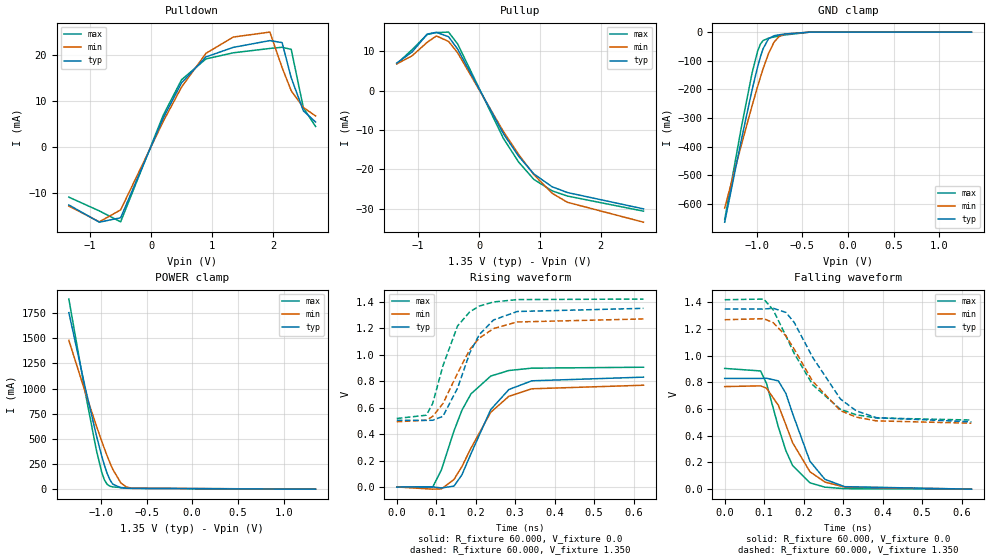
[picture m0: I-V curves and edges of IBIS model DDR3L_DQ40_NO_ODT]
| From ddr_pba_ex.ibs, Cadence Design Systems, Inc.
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|   Model DDR3L_DQ40_NO_ODT
[Model]   DDR3L_DQ40_NO_ODT
Model_type I/O
Polarity   Non-Inverting
Enable   Active-High
Vinl   =   0.624V
Vinh   =   0.727V
C_comp   1.682pF   1.658pF   1.699pF
C_comp_pullup   0.507pF   0.523pF   0.489pF
C_comp_pulldown 1.174pF   1.135pF   1.209pF
[Model Spec]
Vinh   0.727V   NA   NA
Vinl   0.624V   NA   NA
Vmeas   0.675V   NA   NA
[Temperature Range]   27.000   0.125k   -40.000
[Voltage Range]   1.350V   1.270V   1.420V
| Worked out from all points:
|   slope of the pulldown table from 0 to 0.203 V, typ, clamps not added: 31.7 ohm
|   slope of the pullup table from 0 to 0.203 V, typ, clamps not added: 35 ohm
|   GND clamp passes 1 mA (typ) near -0.50 V on its own axis
|   POWER clamp passes 1 mA (typ) near -0.46 V on its own axis
|   rising waveform, R_fixture 60.000, V_fixture 0.0: 20-80 % time 80.6ps typ, 88.1ps min, 74.4ps max; typ from 0 V to 0.83 V
|   rising waveform, R_fixture 60.000, V_fixture 1.350: 20-80 % time 71.4ps typ, 85.1ps min, 61ps max; typ from 0.504 V to 1.35 V
|   falling waveform, R_fixture 60.000, V_fixture 0.0: 20-80 % time 63.1ps typ, 70.8ps min, 58.8ps max; typ from 0.83 V to 0 V
|   falling waveform, R_fixture 60.000, V_fixture 1.350: 20-80 % time 105ps typ, 103ps min, 106ps max; typ from 1.35 V to 0.505 V
[Pulldown]
|Voltage   I(typ)   I(min)   I(max)
-1.35V    -12.71mA   -12.95mA   -11mA
-850mV    -16.48mA   -16.4mA    -14.01mA
-500mV    -15.51mA   -13.79mA   -16.4mA
200mV     6.324mA    5.595mA    6.939mA
500mV     14.01mA    13.08mA    14.69mA
900mV     19.68mA    20.46mA    19.24mA
1.35V     21.77mA    24.03mA    20.58mA
1.95V     23.25mA    25.11mA    21.53mA
2.15V     22.81mA    17.35mA    21.79mA
2.3V      15.11mA    12.27mA    21.33mA
2.5V      7.867mA    8.611mA    8.524mA
2.7V      5.436mA    6.755mA    4.464mA
[Pullup]
|Voltage   I(typ)   I(min)   I(max)
-1.35V    6.994mA    6.778mA    6.785mA
-1.1V     9.771mA    8.81mA     10.37mA
-850mV    14.35mA    12.26mA    14.25mA
-700mV    14.79mA    13.87mA    14.72mA
-500mV    13.68mA    12.48mA    14.85mA
-350mV    10.51mA    9.572mA    11.81mA
400mV     -10.97mA   -10.4mA    -12.15mA
650mV     -16.69mA   -16.24mA   -18.16mA
900mV     -21.19mA   -21.37mA   -22.58mA
1.2V      -24.45mA   -26.1mA    -25.49mA
1.45V     -25.91mA   -28.39mA   -26.8mA
2.7V      -30.07mA   -33.45mA   -30.65mA
[GND_clamp]
|Voltage   I(typ)   I(min)   I(max)
-1.35V    -663.5mA   -614.2mA   -654.4mA
-1.17V    -379.6mA   -396.8mA   -336.4mA
-1.05V    -201.2mA   -256.6mA   -142.3mA
-990mV    -121.8mA   -190.1mA   -66.76mA
-960mV    -87.12mA   -158.5mA   -42.47mA
-930mV    -58.01mA   -128.3mA   -29.57mA
-870mV    -23.03mA   -74.64mA   -21.11mA
-810mV    -12.75mA   -34.94mA   -17.06mA
-750mV    -9.218mA   -14.09mA   -13.42mA
-690mV    -6.687mA   -6.669mA   -9.983mA
-420mV    -175.8uA   -266.9uA   -234.9uA
1.35V     1.792nA    307.1nA    263.8pA
[POWER_clamp]
|Voltage   I(typ)   I(min)   I(max)
-1.35V    1.755A     1.479A     1.89A
-1.17V    1.006A     962.6mA    958.1mA
-1.05V    538.4mA    632.4mA    392.2mA
-990mV    328mA      475.7mA    167mA
-960mV    234.7mA    400.6mA    90.32mA
-930mV    154.2mA    328.7mA    47.17mA
-900mV    91.53mA    260.8mA    29.3mA
-870mV    50.28mA    198.1mA    22.68mA
-780mV    13.3mA     60.49mA    15.94mA
-720mV    9.309mA    21.57mA    12.7mA
-660mV    6.902mA    8.818mA    9.643mA
1.35V     -4.773nA   -193.5nA   -1.001nA
[Ramp]
| variable   typ   min   max
dV/dt_r 0.459/79.597p   0.426/88.799p   0.502/71.616p
dV/dt_f 0.465/0.105n   0.429/0.103n   0.493/0.107n
R_load = 50.000
| The next line is not an IBIS keyword
| [Initial Delay]   0.200ns   0.400ns   0.150ns
[Rising Waveform]
R_fixture= 60.000
V_fixture= 0.0
V_fixture_min= 0.0
V_fixture_max= 0.0
|time   V(typ)   V(min)   V(max)
0s        7.459uV    836.3uV    -14.97uV
91ps      1.618mV    -15.97mV   -121.5uV
113ps     -6.893mV   -14.1mV    129.5mV
145ps     7.183mV    57.71mV    425mV
165ps     92.45mV    155mV      580.1mV
188ps     252mV      293.8mV    704mV
238ps     585.1mV    564.7mV    838.4mV
284ps     736.7mV    685.5mV    880.3mV
342ps     802.5mV    742.2mV    898.1mV
625ps     830.2mV    769.2mV    905.2mV
[Rising Waveform]
R_fixture= 60.000
V_fixture= 1.350
V_fixture_min= 1.270
V_fixture_max= 1.420
|time   V(typ)   V(min)   V(max)
0s        504.2mV    493.4mV    517.9mV
75ps      503.7mV    504.9mV    542.8mV
91ps      504.5mV    533.9mV    631.9mV
117ps     534.6mV    630.8mV    916.3mV
154ps     747.7mV    860.4mV    1.217V
185ps     1.014V     1.039V     1.324V
209ps     1.151V     1.125V     1.367V
245ps     1.262V     1.197V     1.398V
305ps     1.326V     1.247V     1.416V
625ps     1.35V      1.27V      1.42V
[Falling Waveform]
R_fixture= 60.000
V_fixture= 0.0
V_fixture_min= 0.0
V_fixture_max= 0.0
|time   V(typ)   V(min)   V(max)
0s        830.3mV    769mV      905.2mV
91ps      829.9mV    774.5mV    886.1mV
106ps     831.8mV    756.4mV    791.6mV
136ps     811.5mV    628.4mV    465.1mV
155ps     717.2mV    482.5mV    288.6mV
172ps     567mV      348.4mV    177.6mV
216ps     208.9mV    130.3mV    47.46mV
254ps     73.56mV    53.34mV    14.97mV
304ps     18.67mV    16.11mV    3.685mV
625ps     34.77uV    69.72uV    38.66uV
[Falling Waveform]
R_fixture= 60.000
V_fixture= 1.350
V_fixture_min= 1.270
V_fixture_max= 1.420
|time   V(typ)   V(min)   V(max)
0s        1.35V      1.27V      1.42V
99ps      1.35V      1.278V     1.425V
123ps     1.356V     1.248V     1.343V
155ps     1.325V     1.149V     1.149V
176ps     1.25V      1.05V      1.018V
223ps     987.3mV    807.7mV    782mV
293ps     676.2mV    589.1mV    599.1mV
333ps     587.4mV    540.3mV    557.8mV
384ps     536mV      512.1mV    533.7mV
625ps     504.6mV    494.2mV    518.2mV
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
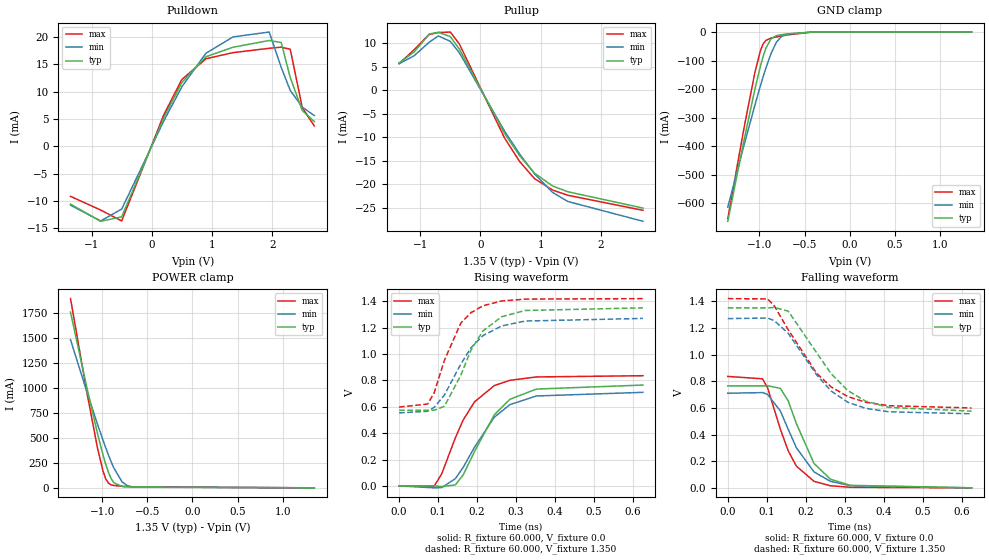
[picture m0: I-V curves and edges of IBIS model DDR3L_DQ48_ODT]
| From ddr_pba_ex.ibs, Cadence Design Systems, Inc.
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|   Model DDR3L_DQ48_ODT
[Model]   DDR3L_DQ48_ODT
Model_type I/O
Polarity   Non-Inverting
Enable   Active-High
Vinl   =   0.624V
Vinh   =   0.727V
C_comp   1.704pF   1.694pF   1.708pF
C_comp_pullup   0.520pF   0.541pF   0.498pF
C_comp_pulldown 1.183pF   1.153pF   1.209pF
[Model Spec]
Vinh   0.727V   NA   NA
Vinl   0.624V   NA   NA
Vmeas   0.675V   NA   NA
[Add Submodel]
|  Submodel_name   Mode
DDR3L_DQ_ODT60   Non-Driving
[Temperature Range]   27.000   0.125k   -40.000
[Voltage Range]   1.350V   1.270V   1.420V
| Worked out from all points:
|   slope of the pulldown table from 0 to 0.203 V, typ, clamps not added: 38 ohm
|   slope of the pullup table from 0 to 0.203 V, typ, clamps not added: 41.9 ohm
|   GND clamp passes 1 mA (typ) near -0.50 V on its own axis
|   POWER clamp passes 1 mA (typ) near -0.46 V on its own axis
|   rising waveform, R_fixture 60.000, V_fixture 0.0: 20-80 % time 89ps typ, 95.7ps min, 83.1ps max; typ from 0 V to 0.765 V
|   rising waveform, R_fixture 60.000, V_fixture 1.350: 20-80 % time 77.7ps typ, 92.1ps min, 67.3ps max; typ from 0.575 V to 1.35 V
|   falling waveform, R_fixture 60.000, V_fixture 0.0: 20-80 % time 68.4ps typ, 76.7ps min, 63.7ps max; typ from 0.765 V to 0 V
|   falling waveform, R_fixture 60.000, V_fixture 1.350: 20-80 % time 117ps typ, 113ps min, 120ps max; typ from 1.35 V to 0.576 V
[Pulldown]
|Voltage   I(typ)   I(min)   I(max)
-1.35V    -10.59mA   -10.79mA   -9.165mA
-850mV    -13.73mA   -13.67mA   -11.67mA
-500mV    -12.92mA   -11.5mA    -13.67mA
200mV     5.271mA    4.664mA    5.784mA
500mV     11.68mA    10.91mA    12.24mA
900mV     16.41mA    17.05mA    16.04mA
1.35V     18.15mA    20.04mA    17.16mA
1.95V     19.38mA    20.93mA    17.95mA
2.15V     19.02mA    14.47mA    18.16mA
2.3V      12.6mA     10.24mA    17.78mA
2.5V      6.561mA    7.181mA    7.107mA
2.7V      4.533mA    5.632mA    3.721mA
[Pullup]
|Voltage   I(typ)   I(min)   I(max)
-1.35V    5.83mA     5.65mA     5.655mA
-1.1V     8.144mA    7.344mA    8.639mA
-850mV    11.96mA    10.22mA    11.87mA
-700mV    12.33mA    11.56mA    12.27mA
-500mV    11.4mA     10.4mA     12.38mA
-350mV    8.759mA    7.978mA    9.845mA
400mV     -9.144mA   -8.667mA   -10.13mA
650mV     -13.91mA   -13.54mA   -15.14mA
900mV     -17.66mA   -17.81mA   -18.82mA
1.2V      -20.38mA   -21.75mA   -21.24mA
1.45V     -21.59mA   -23.66mA   -22.34mA
2.7V      -25.07mA   -27.88mA   -25.55mA
[GND_clamp]
|Voltage   I(typ)   I(min)   I(max)
-1.35V    -663.5mA   -614.2mA   -654.4mA
-1.17V    -379.6mA   -396.8mA   -336.4mA
-1.05V    -201.2mA   -256.6mA   -142.3mA
-990mV    -121.8mA   -190.1mA   -66.76mA
-960mV    -87.12mA   -158.5mA   -42.47mA
-930mV    -58.01mA   -128.3mA   -29.57mA
-870mV    -23.03mA   -74.64mA   -21.11mA
-810mV    -12.75mA   -34.94mA   -17.06mA
-750mV    -9.218mA   -14.09mA   -13.42mA
-690mV    -6.687mA   -6.669mA   -9.983mA
-420mV    -175.8uA   -266.9uA   -234.9uA
1.35V     1.792nA    307.1nA    263.8pA
[POWER_clamp]
|Voltage   I(typ)   I(min)   I(max)
-1.35V    1.755A     1.479A     1.89A
-1.17V    1.006A     962.6mA    958.1mA
-1.05V    538.4mA    632.4mA    392.2mA
-990mV    328mA      475.7mA    167mA
-960mV    234.7mA    400.6mA    90.32mA
-930mV    154.2mA    328.7mA    47.17mA
-900mV    91.53mA    260.8mA    29.3mA
-870mV    50.28mA    198.1mA    22.68mA
-780mV    13.3mA     60.49mA    15.94mA
-720mV    9.309mA    21.57mA    12.7mA
-660mV    6.902mA    8.818mA    9.643mA
1.35V     -4.773nA   -193.5nA   -1.001nA
[Ramp]
| variable   typ   min   max
dV/dt_r 0.419/87.454p   0.390/93.373p   0.458/80.404p
dV/dt_f 0.420/0.116n   0.391/0.112n   0.440/0.119n
R_load = 50.000
| The next line is not an IBIS keyword
| [Initial Delay]   0.200ns   0.400ns   0.150ns
[Rising Waveform]
R_fixture= 60.000
V_fixture= 0.0
V_fixture_min= 0.0
V_fixture_max= 0.0
|time   V(typ)   V(min)   V(max)
0s        8.065uV    771.2uV    -12.06uV
90ps      1.491mV    -13.68mV   917.6uV
109ps     -4.526mV   -11.95mV   91.01mV
144ps     8.599mV    55.57mV    364.3mV
164ps     83.69mV    140.7mV    499.3mV
193ps     259.9mV    293.2mV    636.9mV
244ps     540.3mV    521.5mV    761.1mV
284ps     657.3mV    616.9mV    800.9mV
352ps     734.7mV    682.3mV    826.5mV
625ps     765mV      709.9mV    835.9mV
[Rising Waveform]
R_fixture= 60.000
V_fixture= 1.350
V_fixture_min= 1.270
V_fixture_max= 1.420
|time   V(typ)   V(min)   V(max)
0s        574.5mV    554.4mV    598.4mV
73ps      573.7mV    565.8mV    621.2mV
90ps      574.2mV    596.4mV    707mV
116ps     604.3mV    689.3mV    952.6mV
158ps     838.3mV    923.3mV    1.234V
184ps     1.029V     1.047V     1.313V
215ps     1.176V     1.14V      1.366V
263ps     1.283V     1.213V     1.402V
323ps     1.33V      1.25V      1.416V
625ps     1.35V      1.27V      1.42V
[Falling Waveform]
R_fixture= 60.000
V_fixture= 0.0
V_fixture_min= 0.0
V_fixture_max= 0.0
|time   V(typ)   V(min)   V(max)
0s        765.2mV    710mV      836mV
89ps      764.9mV    714.6mV    818.3mV
102ps     766.2mV    701.3mV    751.4mV
135ps     746.2mV    576.1mV    438.4mV
155ps     652.3mV    438.9mV    277.7mV
176ps     481.6mV    300.5mV    162.7mV
221ps     183.4mV    119.9mV    49.01mV
263ps     65.3mV     49.31mV    15.75mV
314ps     18.8mV     16.37mV    4.308mV
625ps     42.97uV    88.37uV    39.85uV
[Falling Waveform]
R_fixture= 60.000
V_fixture= 1.350
V_fixture_min= 1.270
V_fixture_max= 1.420
|time   V(typ)   V(min)   V(max)
0s        1.35V      1.27V      1.42V
102ps     1.35V      1.274V     1.418V
119ps     1.354V     1.255V     1.367V
155ps     1.326V     1.159V     1.186V
228ps     1.013V     847.6mV    859mV
265ps     856.5mV    726.3mV    757.3mV
308ps     729.2mV    641.9mV    684.6mV
353ps     650.9mV    597mV      642.5mV
413ps     603.6mV    570.6mV    616.1mV
625ps     575.5mV    555.6mV    599.2mV
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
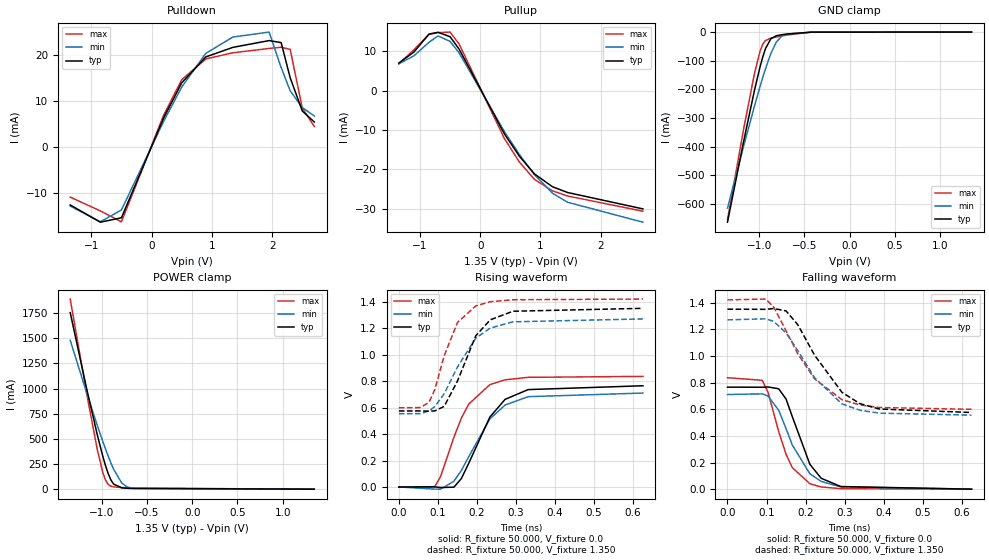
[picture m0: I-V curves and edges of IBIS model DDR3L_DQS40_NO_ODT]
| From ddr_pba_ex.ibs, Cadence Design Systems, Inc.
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|   Model DDR3L_DQS40_NO_ODT
[Model]   DDR3L_DQS40_NO_ODT
Model_type I/O
Polarity   Non-Inverting
Enable   Active-High
Vinl   =   0.624V
Vinh   =   0.727V
C_comp   1.684pF   1.658pF   1.703pF
C_comp_pullup   0.506pF   0.522pF   0.489pF
C_comp_pulldown 1.177pF   1.136pF   1.213pF
[Model Spec]
Vinh   0.727V   NA   NA
Vinl   0.624V   NA   NA
Vmeas   0.675V   NA   NA
[Temperature Range]   27.000   0.125k   -40.000
[Voltage Range]   1.350V   1.270V   1.420V
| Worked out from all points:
|   slope of the pulldown table from 0 to 0.203 V, typ, clamps not added: 31.7 ohm
|   slope of the pullup table from 0 to 0.203 V, typ, clamps not added: 35 ohm
|   GND clamp passes 1 mA (typ) near -0.50 V on its own axis
|   POWER clamp passes 1 mA (typ) near -0.46 V on its own axis
|   rising waveform, R_fixture 50.000, V_fixture 0.0: 20-80 % time 78.8ps typ, 86.4ps min, 71.6ps max; typ from 0 V to 0.765 V
|   rising waveform, R_fixture 50.000, V_fixture 1.350: 20-80 % time 68.6ps typ, 82.9ps min, 58.3ps max; typ from 0.575 V to 1.35 V
|   falling waveform, R_fixture 50.000, V_fixture 0.0: 20-80 % time 59.7ps typ, 67.6ps min, 55.4ps max; typ from 0.765 V to 0 V
|   falling waveform, R_fixture 50.000, V_fixture 1.350: 20-80 % time 104ps typ, 102ps min, 106ps max; typ from 1.35 V to 0.575 V
[Pulldown]
|Voltage   I(typ)   I(min)   I(max)
-1.35V    -12.71mA   -12.95mA   -11mA
-850mV    -16.48mA   -16.4mA    -14.01mA
-500mV    -15.51mA   -13.79mA   -16.4mA
200mV     6.324mA    5.595mA    6.939mA
500mV     14.01mA    13.08mA    14.69mA
900mV     19.68mA    20.46mA    19.24mA
1.35V     21.77mA    24.03mA    20.58mA
1.95V     23.25mA    25.11mA    21.53mA
2.15V     22.81mA    17.35mA    21.79mA
2.3V      15.11mA    12.27mA    21.33mA
2.5V      7.867mA    8.611mA    8.524mA
2.7V      5.436mA    6.755mA    4.464mA
[Pullup]
|Voltage   I(typ)   I(min)   I(max)
-1.35V    6.994mA    6.778mA    6.785mA
-1.1V     9.771mA    8.81mA     10.37mA
-850mV    14.35mA    12.26mA    14.25mA
-700mV    14.79mA    13.87mA    14.72mA
-500mV    13.68mA    12.48mA    14.85mA
-350mV    10.51mA    9.572mA    11.81mA
400mV     -10.97mA   -10.4mA    -12.15mA
650mV     -16.69mA   -16.24mA   -18.16mA
900mV     -21.19mA   -21.37mA   -22.58mA
1.2V      -24.45mA   -26.1mA    -25.49mA
1.45V     -25.91mA   -28.39mA   -26.8mA
2.7V      -30.07mA   -33.45mA   -30.65mA
[GND_clamp]
|Voltage   I(typ)   I(min)   I(max)
-1.35V    -663.5mA   -614.2mA   -654.4mA
-1.17V    -379.6mA   -396.8mA   -336.4mA
-1.05V    -201.2mA   -256.6mA   -142.3mA
-990mV    -121.8mA   -190.1mA   -66.76mA
-960mV    -87.12mA   -158.5mA   -42.47mA
-930mV    -58.01mA   -128.3mA   -29.57mA
-870mV    -23.03mA   -74.64mA   -21.11mA
-810mV    -12.75mA   -34.94mA   -17.06mA
-750mV    -9.219mA   -14.09mA   -13.42mA
-690mV    -6.687mA   -6.669mA   -9.983mA
-420mV    -175.8uA   -266.9uA   -234.9uA
1.35V     1.781nA    307.1nA    267.4pA
[POWER_clamp]
|Voltage   I(typ)   I(min)   I(max)
-1.35V    1.755A     1.479A     1.89A
-1.17V    1.006A     962.6mA    958.1mA
-1.05V    538.4mA    632.4mA    392.2mA
-990mV    328mA      475.7mA    167mA
-960mV    234.7mA    400.6mA    90.32mA
-930mV    154.2mA    328.7mA    47.17mA
-900mV    91.53mA    260.8mA    29.3mA
-870mV    50.28mA    198.1mA    22.68mA
-780mV    13.3mA     60.49mA    15.94mA
-720mV    9.309mA    21.57mA    12.7mA
-660mV    6.902mA    8.818mA    9.643mA
1.35V     -4.773nA   -193.5nA   -1nA
[Ramp]
| variable   typ   min   max
dV/dt_r 0.459/79.862p   0.426/87.109p   0.502/73.280p
dV/dt_f 0.465/0.106n   0.429/0.104n   0.493/0.108n
R_load = 50.000
| The next line is not an IBIS keyword
| [Initial Delay]   0.200ns   0.400ns   0.150ns
[Rising Waveform]
R_fixture= 50.000
V_fixture= 0.0
V_fixture_min= 0.0
V_fixture_max= 0.0
|time   V(typ)   V(min)   V(max)
0s        6.488uV    823.9uV    -14.21uV
92ps      1.282mV    -15.85mV   3.07mV
107ps     -3.761mV   -16.06mV   80.39mV
141ps     -883.8uV   43.86mV    376mV
160ps     63.79mV    125.2mV    520.2mV
179ps     180mV      229.5mV    626.7mV
233ps     528.4mV    514.1mV    773.3mV
272ps     662.3mV    619.2mV    809.9mV
331ps     736.1mV    682.6mV    828.7mV
625ps     765.1mV    710mV      835.9mV
[Rising Waveform]
R_fixture= 50.000
V_fixture= 1.350
V_fixture_min= 1.270
V_fixture_max= 1.420
|time   V(typ)   V(min)   V(max)
0s        574.7mV    554.4mV    598.5mV
55ps      574.7mV    554.1mV    600.6mV
77ps      573.4mV    574.5mV    639.2mV
92ps      575.2mV    607.5mV    735.4mV
116ps     609mV      704mV      990.9mV
150ps     799.9mV    906.5mV    1.243V
197ps     1.143V     1.125V     1.368V
234ps     1.263V     1.201V     1.4V
292ps     1.328V     1.248V     1.415V
625ps     1.35V      1.27V      1.42V
[Falling Waveform]
R_fixture= 50.000
V_fixture= 0.0
V_fixture_min= 0.0
V_fixture_max= 0.0
|time   V(typ)   V(min)   V(max)
0s        765.2mV    709.9mV    835.9mV
89ps      764.7mV    715mV      816.8mV
104ps     766.5mV    698.1mV    725.4mV
131ps     753.2mV    592.7mV    433.6mV
150ps     676.2mV    454.8mV    261.8mV
166ps     544.1mV    331.2mV    161.6mV
211ps     186.5mV    115.4mV    40.48mV
240ps     81.86mV    57.68mV    16.52mV
290ps     19.7mV     17.21mV    3.851mV
625ps     29.82uV    61.65uV    34.44uV
[Falling Waveform]
R_fixture= 50.000
V_fixture= 1.350
V_fixture_min= 1.270
V_fixture_max= 1.420
|time   V(typ)   V(min)   V(max)
0s        1.35V      1.27V      1.42V
98ps      1.349V     1.278V     1.426V
119ps     1.355V     1.257V     1.363V
150ps     1.337V     1.172V     1.188V
180ps     1.234V     1.04V      1.015V
223ps     1.005V     835.7mV    827.6mV
293ps     726.9mV    639.6mV    671.3mV
339ps     641.7mV    592.2mV    631.8mV
389ps     601.2mV    570.1mV    612.5mV
625ps     575.1mV    555.3mV    598.8mV
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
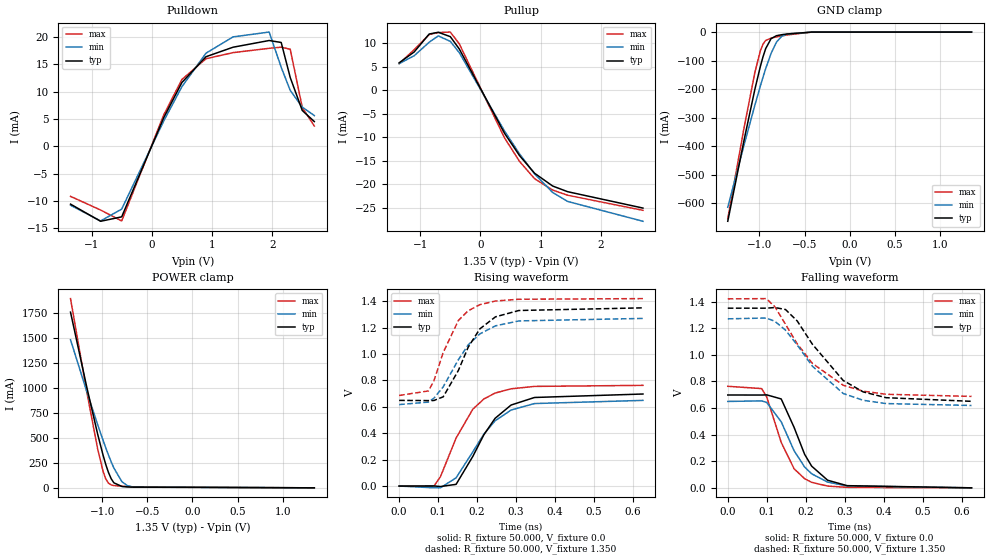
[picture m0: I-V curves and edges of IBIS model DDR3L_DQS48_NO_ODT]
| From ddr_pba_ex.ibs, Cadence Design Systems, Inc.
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|   Model DDR3L_DQS48_NO_ODT
[Model]   DDR3L_DQS48_NO_ODT
Model_type I/O
Polarity   Non-Inverting
Enable   Active-High
Vinl   =   0.624V
Vinh   =   0.727V
C_comp   1.706pF   1.695pF   1.713pF
C_comp_pullup   0.519pF   0.540pF   0.498pF
C_comp_pulldown 1.187pF   1.155pF   1.214pF
[Model Spec]
Vinh   0.727V   NA   NA
Vinl   0.624V   NA   NA
Vmeas   0.675V   NA   NA
[Temperature Range]   27.000   0.125k   -40.000
[Voltage Range]   1.350V   1.270V   1.420V
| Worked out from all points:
|   slope of the pulldown table from 0 to 0.203 V, typ, clamps not added: 38 ohm
|   slope of the pullup table from 0 to 0.203 V, typ, clamps not added: 41.9 ohm
|   GND clamp passes 1 mA (typ) near -0.50 V on its own axis
|   POWER clamp passes 1 mA (typ) near -0.46 V on its own axis
|   rising waveform, R_fixture 50.000, V_fixture 0.0: 20-80 % time 86.1ps typ, 93.4ps min, 80ps max; typ from 0 V to 0.698 V
|   rising waveform, R_fixture 50.000, V_fixture 1.350: 20-80 % time 74.1ps typ, 88.6ps min, 63.5ps max; typ from 0.649 V to 1.35 V
|   falling waveform, R_fixture 50.000, V_fixture 0.0: 20-80 % time 64.1ps typ, 72.5ps min, 59.4ps max; typ from 0.698 V to 0 V
|   falling waveform, R_fixture 50.000, V_fixture 1.350: 20-80 % time 115ps typ, 112ps min, 117ps max; typ from 1.35 V to 0.65 V
[Pulldown]
|Voltage   I(typ)   I(min)   I(max)
-1.35V    -10.59mA   -10.79mA   -9.165mA
-850mV    -13.73mA   -13.67mA   -11.67mA
-500mV    -12.92mA   -11.5mA    -13.67mA
200mV     5.271mA    4.664mA    5.784mA
500mV     11.68mA    10.91mA    12.24mA
900mV     16.41mA    17.05mA    16.04mA
1.35V     18.15mA    20.04mA    17.16mA
1.95V     19.38mA    20.93mA    17.95mA
2.15V     19.02mA    14.47mA    18.16mA
2.3V      12.6mA     10.24mA    17.78mA
2.5V      6.561mA    7.181mA    7.107mA
2.7V      4.533mA    5.632mA    3.721mA
[Pullup]
|Voltage   I(typ)   I(min)   I(max)
-1.35V    5.83mA     5.65mA     5.655mA
-1.1V     8.144mA    7.344mA    8.639mA
-850mV    11.96mA    10.22mA    11.87mA
-700mV    12.33mA    11.56mA    12.27mA
-500mV    11.4mA     10.4mA     12.38mA
-350mV    8.759mA    7.978mA    9.845mA
400mV     -9.144mA   -8.667mA   -10.13mA
650mV     -13.91mA   -13.54mA   -15.14mA
900mV     -17.66mA   -17.81mA   -18.82mA
1.2V      -20.38mA   -21.75mA   -21.24mA
1.45V     -21.59mA   -23.66mA   -22.34mA
2.7V      -25.07mA   -27.88mA   -25.55mA
[GND_clamp]
|Voltage   I(typ)   I(min)   I(max)
-1.35V    -663.5mA   -614.2mA   -654.4mA
-1.17V    -379.6mA   -396.8mA   -336.4mA
-1.05V    -201.2mA   -256.6mA   -142.3mA
-990mV    -121.8mA   -190.1mA   -66.76mA
-960mV    -87.12mA   -158.5mA   -42.47mA
-930mV    -58.01mA   -128.3mA   -29.57mA
-870mV    -23.03mA   -74.64mA   -21.11mA
-810mV    -12.75mA   -34.94mA   -17.06mA
-750mV    -9.219mA   -14.09mA   -13.42mA
-690mV    -6.687mA   -6.669mA   -9.983mA
-420mV    -175.8uA   -266.9uA   -234.9uA
1.35V     1.781nA    307.1nA    267.4pA
[POWER_clamp]
|Voltage   I(typ)   I(min)   I(max)
-1.35V    1.755A     1.479A     1.89A
-1.17V    1.006A     962.6mA    958.1mA
-1.05V    538.4mA    632.4mA    392.2mA
-990mV    328mA      475.7mA    167mA
-960mV    234.7mA    400.6mA    90.32mA
-930mV    154.2mA    328.7mA    47.17mA
-900mV    91.53mA    260.8mA    29.3mA
-870mV    50.28mA    198.1mA    22.68mA
-780mV    13.3mA     60.49mA    15.94mA
-720mV    9.309mA    21.57mA    12.7mA
-660mV    6.902mA    8.818mA    9.643mA
1.35V     -4.773nA   -193.5nA   -1nA
[Ramp]
| variable   typ   min   max
dV/dt_r 0.419/87.445p   0.390/95.365p   0.458/80.180p
dV/dt_f 0.420/0.116n   0.391/0.114n   0.440/0.119n
R_load = 50.000
| The next line is not an IBIS keyword
| [Initial Delay]   0.200ns   0.400ns   0.150ns
[Rising Waveform]
R_fixture= 50.000
V_fixture= 0.0
V_fixture_min= 0.0
V_fixture_max= 0.0
|time   V(typ)   V(min)   V(max)
0s        7.093uV    758.7uV    -11.55uV
89ps      1.522mV    -13.03mV   -944.6uV
106ps     -3.18mV    -12.7mV    71.64mV
146ps     13.44mV    62.81mV    364.4mV
189ps     225.5mV    260.1mV    583mV
217ps     387.8mV    393.2mV    659.3mV
246ps     513.5mV    494.7mV    704.9mV
287ps     614mV      576.2mV    736.9mV
347ps     671.2mV    625.2mV    755.1mV
625ps     697.5mV    649.2mV    763mV
[Rising Waveform]
R_fixture= 50.000
V_fixture= 1.350
V_fixture_min= 1.270
V_fixture_max= 1.420
|time   V(typ)   V(min)   V(max)
0s        649.2mV    617.5mV    686.2mV
75ps      647.6mV    636.3mV    720.7mV
89ps      648.2mV    665.7mV    796.4mV
113ps     676.2mV    751.9mV    1.012V
152ps     876.8mV    958.1mV    1.255V
177ps     1.052V     1.069V     1.328V
207ps     1.191V     1.153V     1.374V
247ps     1.282V     1.214V     1.402V
307ps     1.33V      1.251V     1.415V
625ps     1.35V      1.27V      1.42V
[Falling Waveform]
R_fixture= 50.000
V_fixture= 0.0
V_fixture_min= 0.0
V_fixture_max= 0.0
|time   V(typ)   V(min)   V(max)
0s        697.7mV    649.2mV    763.1mV
87ps      697.3mV    653.5mV    745.8mV
100ps     698.6mV    641.1mV    682mV
137ps     668mV      496.6mV    341.9mV
170ps     454.5mV    279mV      143.5mV
197ps     252.1mV    156.6mV    68.7mV
215ps     163.2mV    105.7mV    41.46mV
256ps     57.11mV    43.2mV     13.27mV
306ps     16.34mV    14.34mV    3.665mV
625ps     34.52uV    71.96uV    34.34uV
[Falling Waveform]
R_fixture= 50.000
V_fixture= 1.350
V_fixture_min= 1.270
V_fixture_max= 1.420
|time   V(typ)   V(min)   V(max)
0s        1.35V      1.27V      1.42V
99ps      1.35V      1.276V     1.422V
121ps     1.355V     1.251V     1.36V
148ps     1.34V      1.185V     1.229V
178ps     1.254V     1.074V     1.083V
217ps     1.079V     913.9mV    934.8mV
296ps     806.6mV    709mV      770.9mV
347ps     721.2mV    658mV      726.5mV
406ps     677.4mV    633.2mV    703.1mV
625ps     650.1mV    618.9mV    687mV
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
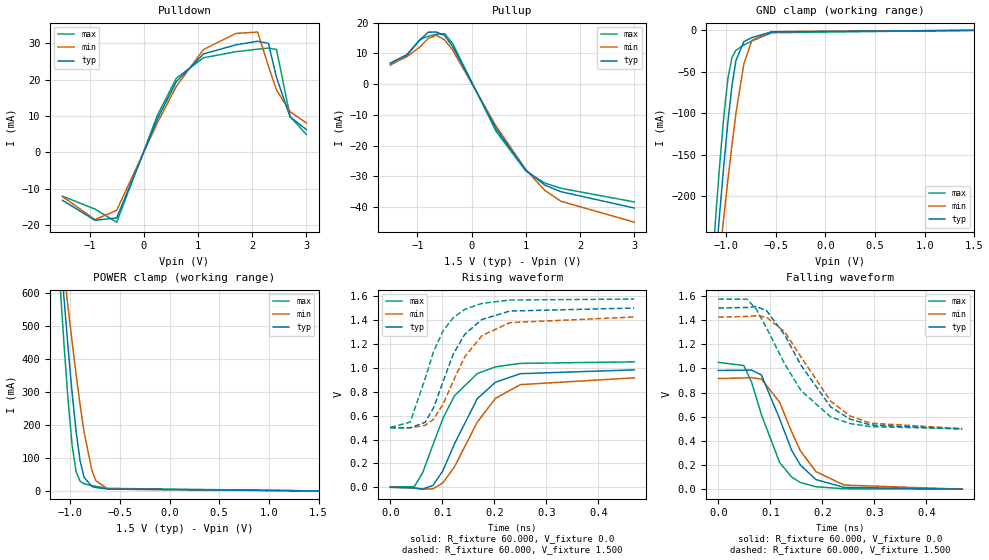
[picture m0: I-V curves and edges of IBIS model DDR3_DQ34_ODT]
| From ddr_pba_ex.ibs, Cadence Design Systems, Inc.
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|   Model DDR3_DQ34_ODT
[Model]   DDR3_DQ34_ODT
Model_type I/O
Polarity   Non-Inverting
Enable   Active-High
Vinl   =   0.575V
Vinh   =   0.925V
C_comp   1.612pF   1.592pF   1.671pF
C_comp_pullup   0.459pF   0.494pF   0.467pF
C_comp_pulldown 1.152pF   1.097pF   1.204pF
[Model Spec]
Vinh   0.925V   NA   NA
Vinl   0.575V   NA   NA
Vmeas   0.750V   NA   NA
[Add Submodel]
|  Submodel_name   Mode
DDR3_DQ_ODT60   Non-Driving
[Temperature Range]   27.000   0.125k   -40.000
[Voltage Range]   1.500V   1.425V   1.575V
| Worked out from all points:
|   slope of the pulldown table from 0 to 0.225 V, typ, clamps not added: 27.2 ohm
|   slope of the pullup table from 0 to 0.225 V, typ, clamps not added: 29.9 ohm
|   GND clamp passes 1 mA (typ) near -0.50 V on its own axis
|   POWER clamp passes 1 mA (typ) near -0.45 V on its own axis
|   rising waveform, R_fixture 60.000, V_fixture 0.0: 20-80 % time 68.7ps typ, 74.1ps min, 66ps max; typ from 0 V to 0.983 V
|   rising waveform, R_fixture 60.000, V_fixture 1.500: 20-80 % time 60.9ps typ, 68.7ps min, 55ps max; typ from 0.497 V to 1.5 V
|   falling waveform, R_fixture 60.000, V_fixture 0.0: 20-80 % time 56.7ps typ, 62.8ps min, 52ps max; typ from 0.983 V to 0 V
|   falling waveform, R_fixture 60.000, V_fixture 1.500: 20-80 % time 87ps typ, 87.9ps min, 89.7ps max; typ from 1.5 V to 0.498 V
[Pulldown]
|Voltage   I(typ)   I(min)   I(max)
-1.5V     -13.11mA   -12.09mA   -11.99mA
-900mV    -18.6mA    -18.43mA   -15.54mA
-500mV    -17.95mA   -15.85mA   -19.12mA
250mV     9.123mA    8.086mA    10.11mA
600mV     19.39mA    18.08mA    20.34mA
1.1V      27mA       28.19mA    25.96mA
1.7V      29.51mA    32.65mA    27.63mA
2.1V      30.49mA    33.01mA    28.32mA
2.3V      29.93mA    23.73mA    28.62mA
2.45V     20.53mA    17.11mA    28.23mA
2.7V      9.751mA    11.19mA    9.851mA
3V        6.277mA    8.093mA    4.942mA
[Pullup]
|Voltage   I(typ)   I(min)   I(max)
-1.5V     6.892mA    6.626mA    6.196mA
-1.2V     9.586mA    8.882mA    9.221mA
-950mV    14.51mA    12.17mA    14.57mA
-800mV    16.94mA    14.89mA    15.59mA
-650mV    16.95mA    15.91mA    16.25mA
-500mV    15.86mA    14.42mA    16.44mA
-350mV    12.21mA    11.08mA    13.19mA
450mV     -14.47mA   -13.63mA   -15.32mA
1V        -27.96mA   -27.83mA   -28.29mA
1.35V     -32.83mA   -34.57mA   -32.17mA
1.65V     -34.98mA   -38.1mA    -33.88mA
3V        -40.28mA   -44.89mA   -38.3mA
[GND_clamp]
|Voltage   I(typ)   I(min)   I(max)
-1.5V     -902.4mA   -795.2mA   -923mA
-1.14V    -333.6mA   -361.2mA   -285.4mA
-1.1V     -273.5mA   -314.1mA   -219.4mA
-1.06V    -215.4mA   -267.9mA   -157.1mA
-1.02V    -160.2mA   -222.9mA   -101.2mA
-980mV    -109.7mA   -179.4mA   -57.37mA
-940mV    -66.97mA   -138.2mA   -32.78mA
-900mV    -36.37mA   -100.2mA   -23.99mA
-820mV    -13.67mA   -40.29mA   -17.69mA
-740mV    -8.766mA   -12.21mA   -12.83mA
-540mV    -1.803mA   -1.643mA   -2.86mA
1.5V      1.911nA    275.5nA    464.3pA
[POWER_clamp]
|Voltage   I(typ)   I(min)   I(max)
-1.5V     2.395A     1.917A     2.689A
-1.1V     728.2mA    767.9mA    617.4mA
-1.06V    575.5mA    659.2mA    435.4mA
-1.02V    430.1mA    553.1mA    270.8mA
-980mV    295.8mA    450.4mA    137.9mA
-940mV    179.3mA    352.3mA    58.02mA
-900mV    91.53mA    260.8mA    29.3mA
-860mV    41.11mA    178.7mA    21.47mA
-780mV    13.3mA     60.49mA    15.94mA
-740mV    10.3mA     30.45mA    13.76mA
-620mV    5.486mA    5.676mA    7.71mA
1.5V      -5.523nA   -199nA     -1.165nA
[Ramp]
| variable   typ   min   max
dV/dt_r 0.549/66.986p   0.512/74.961p   0.586/65.401p
dV/dt_f 0.559/88.075p   0.516/88.502p   0.597/91.251p
R_load = 50.000
| The next line is not an IBIS keyword
| [Initial Delay]   0.225ns   0.350ns   0.175ns
[Rising Waveform]
R_fixture= 60.000
V_fixture= 0.0
V_fixture_min= 0.0
V_fixture_max= 0.0
|time   V(typ)   V(min)   V(max)
0s        462.5uV    1.599mV    3.085mV
46ps      -4.213mV   -6.217mV   6.451mV
62ps      -14.35mV   -14.98mV   121.4mV
82ps      16.7mV     -11.93mV   358.3mV
101ps     139.8mV    38.3mV     575.7mV
123ps     362.1mV    170.2mV    764.9mV
167ps     741.2mV    544.4mV    951.4mV
202ps     879.4mV    744.7mV    1.008V
250ps     950.8mV    859.3mV    1.037V
469ps     983.1mV    916.3mV    1.05V
[Rising Waveform]
R_fixture= 60.000
V_fixture= 1.500
V_fixture_min= 1.425
V_fixture_max= 1.575
|time   V(typ)   V(min)   V(max)
0s        497.3mV    500.3mV    501.9mV
38ps      498.6mV    498.6mV    545.4mV
67ps      544.5mV    519mV      911.4mV
83ps      665.6mV    568.7mV    1.136V
102ps     893.3mV    701.5mV    1.314V
121ps     1.115V     890.8mV    1.419V
143ps     1.28V      1.093V     1.489V
176ps     1.404V     1.269V     1.539V
230ps     1.475V     1.378V     1.567V
469ps     1.5V       1.425V     1.575V
[Falling Waveform]
R_fixture= 60.000
V_fixture= 0.0
V_fixture_min= 0.0
V_fixture_max= 0.0
|time   V(typ)   V(min)   V(max)
0s        983.4mV    916.2mV    1.05V
49ps      984.9mV    920.7mV    1.024V
64ps      986.9mV    923.7mV    886.6mV
83ps      944.7mV    911.5mV    615.7mV
118ps     582.1mV    719.3mV    220.2mV
141ps     322.6mV    475.2mV    100.8mV
158ps     198.7mV    315.9mV    54.87mV
188ps     79.17mV    144.7mV    20.02mV
242ps     14.8mV     33.96mV    3.478mV
469ps     191.3uV    131uV      96.01uV
[Falling Waveform]
R_fixture= 60.000
V_fixture= 1.500
V_fixture_min= 1.425
V_fixture_max= 1.575
|time   V(typ)   V(min)   V(max)
0s        1.5V       1.424V     1.574V
55ps      1.504V     1.43V      1.573V
73ps      1.512V     1.436V     1.491V
93ps      1.478V     1.423V     1.333V
128ps     1.274V     1.301V     1.034V
159ps     1.026V     1.095V     817mV
216ps     681.3mV    729.3mV    598.7mV
253ps     580.4mV    606.3mV    543.3mV
293ps     531.3mV    546.6mV    518mV
469ps     497.9mV    501.4mV    500.2mV
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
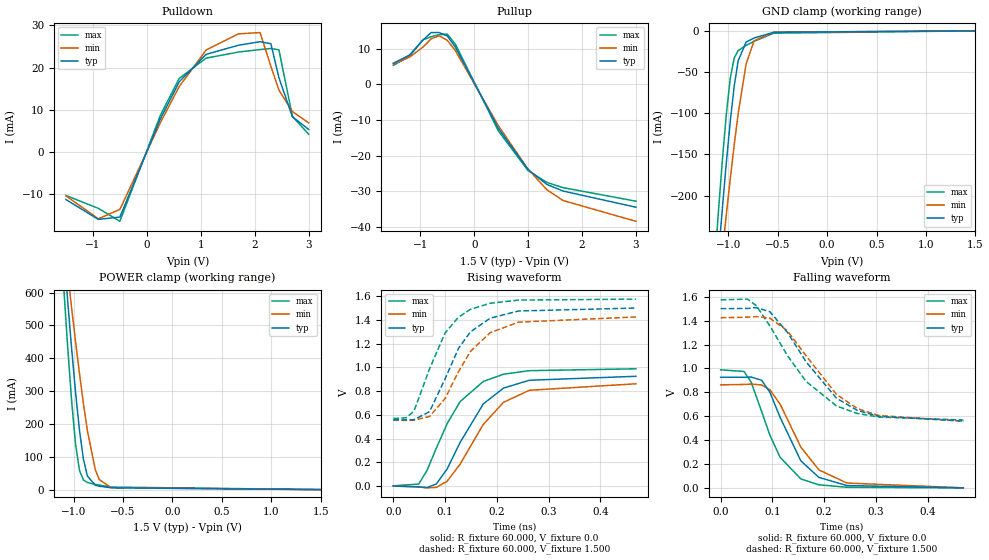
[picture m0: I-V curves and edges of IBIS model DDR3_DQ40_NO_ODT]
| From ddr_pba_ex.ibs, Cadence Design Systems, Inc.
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|   Model DDR3_DQ40_NO_ODT
[Model]   DDR3_DQ40_NO_ODT
Model_type I/O
Polarity   Non-Inverting
Enable   Active-High
Vinl   =   0.575V
Vinh   =   0.925V
C_comp   1.638pF   1.631pF   1.684pF
C_comp_pullup   0.472pF   0.512pF   0.476pF
C_comp_pulldown 1.166pF   1.118pF   1.207pF
[Model Spec]
Vinh   0.925V   NA   NA
Vinl   0.575V   NA   NA
Vmeas   0.750V   NA   NA
[Temperature Range]   27.000   0.125k   -40.000
[Voltage Range]   1.500V   1.425V   1.575V
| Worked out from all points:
|   slope of the pulldown table from 0 to 0.225 V, typ, clamps not added: 31.8 ohm
|   slope of the pullup table from 0 to 0.225 V, typ, clamps not added: 34.8 ohm
|   GND clamp passes 1 mA (typ) near -0.50 V on its own axis
|   POWER clamp passes 1 mA (typ) near -0.45 V on its own axis
|   rising waveform, R_fixture 60.000, V_fixture 0.0: 20-80 % time 75.7ps typ, 80.9ps min, 73.4ps max; typ from 0 V to 0.925 V
|   rising waveform, R_fixture 60.000, V_fixture 1.500: 20-80 % time 66.6ps typ, 75.2ps min, 60.6ps max; typ from 0.558 V to 1.5 V
|   falling waveform, R_fixture 60.000, V_fixture 0.0: 20-80 % time 61.5ps typ, 68.2ps min, 56.2ps max; typ from 0.926 V to 0 V
|   falling waveform, R_fixture 60.000, V_fixture 1.500: 20-80 % time 97.3ps typ, 96.9ps min, 101ps max; typ from 1.5 V to 0.56 V
[Pulldown]
|Voltage   I(typ)   I(min)   I(max)
-1.5V     -11.24mA   -10.36mA   -10.27mA
-900mV    -15.94mA   -15.8mA    -13.32mA
-500mV    -15.38mA   -13.58mA   -16.39mA
250mV     7.818mA    6.93mA     8.666mA
600mV     16.62mA    15.5mA     17.43mA
1.1V      23.14mA    24.16mA    22.24mA
1.7V      25.29mA    27.98mA    23.68mA
2.1V      26.12mA    28.29mA    24.27mA
2.3V      25.65mA    20.33mA    24.52mA
2.45V     17.59mA    14.66mA    24.19mA
2.7V      8.354mA    9.586mA    8.44mA
3V        5.378mA    6.93mA     4.234mA
[Pullup]
|Voltage   I(typ)   I(min)   I(max)
-1.5V     5.907mA    5.675mA    5.31mA
-1.2V     8.216mA    7.612mA    7.902mA
-950mV    12.44mA    10.43mA    12.49mA
-800mV    14.52mA    12.76mA    13.36mA
-650mV    14.53mA    13.64mA    13.93mA
-500mV    13.59mA    12.36mA    14.09mA
-350mV    10.47mA    9.5mA      11.3mA
450mV     -12.4mA    -11.68mA   -13.13mA
1V        -23.97mA   -23.85mA   -24.24mA
1.35V     -28.14mA   -29.63mA   -27.57mA
1.65V     -29.98mA   -32.65mA   -29.03mA
3V        -34.52mA   -38.47mA   -32.82mA
[GND_clamp]
|Voltage   I(typ)   I(min)   I(max)
-1.5V     -902.4mA   -795.2mA   -923mA
-1.14V    -333.6mA   -361.2mA   -285.4mA
-1.1V     -273.5mA   -314.1mA   -219.4mA
-1.06V    -215.4mA   -267.9mA   -157.1mA
-1.02V    -160.2mA   -222.9mA   -101.2mA
-980mV    -109.7mA   -179.4mA   -57.37mA
-940mV    -66.97mA   -138.2mA   -32.78mA
-900mV    -36.37mA   -100.2mA   -23.99mA
-820mV    -13.67mA   -40.29mA   -17.69mA
-740mV    -8.766mA   -12.21mA   -12.83mA
-540mV    -1.803mA   -1.643mA   -2.86mA
1.5V      1.911nA    275.5nA    464.3pA
[POWER_clamp]
|Voltage   I(typ)   I(min)   I(max)
-1.5V     2.395A     1.917A     2.689A
-1.1V     728.2mA    767.9mA    617.4mA
-1.06V    575.5mA    659.2mA    435.4mA
-1.02V    430.1mA    553.1mA    270.8mA
-980mV    295.8mA    450.4mA    137.9mA
-940mV    179.3mA    352.3mA    58.02mA
-900mV    91.53mA    260.8mA    29.3mA
-860mV    41.11mA    178.7mA    21.47mA
-780mV    13.3mA     60.49mA    15.94mA
-740mV    10.3mA     30.45mA    13.76mA
-620mV    5.486mA    5.676mA    7.71mA
1.5V      -5.523nA   -199nA     -1.165nA
[Ramp]
| variable   typ   min   max
dV/dt_r 0.512/74.010p   0.478/79.034p   0.547/72.510p
dV/dt_f 0.519/98.123p   0.481/97.436p   0.552/0.103n
R_load = 50.000
| The next line is not an IBIS keyword
| [Initial Delay]   0.225ns   0.350ns   0.175ns
[Rising Waveform]
R_fixture= 60.000
V_fixture= 0.0
V_fixture_min= 0.0
V_fixture_max= 0.0
|time   V(typ)   V(min)   V(max)
0s        444.9uV    1.426mV    2.714mV
49ps      -5.731mV   -6.987mV   17.22mV
65ps      -12.42mV   -14.54mV   130.8mV
83ps      17.74mV    -10.69mV   317.8mV
104ps     144.4mV    40.97mV    525.8mV
129ps     366.6mV    184.4mV    711.2mV
174ps     692.8mV    520.4mV    882mV
213ps     825.7mV    706mV      942.7mV
263ps     891.8mV    807.3mV    972.5mV
469ps     925.1mV    862mV      988.2mV
[Rising Waveform]
R_fixture= 60.000
V_fixture= 1.500
V_fixture_min= 1.425
V_fixture_max= 1.575
|time   V(typ)   V(min)   V(max)
0s        557.8mV    555.3mV    569mV
25ps      558.4mV    553.8mV    576.4mV
40ps      560.1mV    555.2mV    631.9mV
70ps      626.8mV    586.5mV    986.6mV
100ps     903.9mV    737mV      1.29V
126ps     1.16V      964.3mV    1.423V
149ps     1.299V     1.134V     1.489V
187ps     1.414V     1.292V     1.54V
242ps     1.475V     1.381V     1.567V
469ps     1.5V       1.425V     1.575V
[Falling Waveform]
R_fixture= 60.000
V_fixture= 0.0
V_fixture_min= 0.0
V_fixture_max= 0.0
|time   V(typ)   V(min)   V(max)
0s        925.6mV    862.4mV    987.7mV
45ps      926.2mV    865.7mV    974.7mV
59ps      927.8mV    868.5mV    884.7mV
79ps      900.9mV    861.9mV    641.5mV
95ps      801.8mV    822mV      442.6mV
115ps     589.6mV    699.7mV    255.2mV
155ps     226mV      340.9mV    74.62mV
190ps     87.42mV    150.2mV    25.47mV
244ps     19.35mV    40.51mV    5.087mV
469ps     222uV      223.9uV    102.7uV
[Falling Waveform]
R_fixture= 60.000
V_fixture= 1.500
V_fixture_min= 1.425
V_fixture_max= 1.575
|time   V(typ)   V(min)   V(max)
0s        1.5V       1.424V     1.574V
52ps      1.502V     1.429V     1.58V
69ps      1.509V     1.434V     1.525V
95ps      1.475V     1.421V     1.357V
129ps     1.302V     1.315V     1.108V
165ps     1.056V     1.106V     891.2mV
224ps     750.2mV    782mV      685.5mV
264ps     649.3mV    664.2mV    623mV
305ps     598.8mV    606.2mV    593.1mV
469ps     559.5mV    557.8mV    568.5mV
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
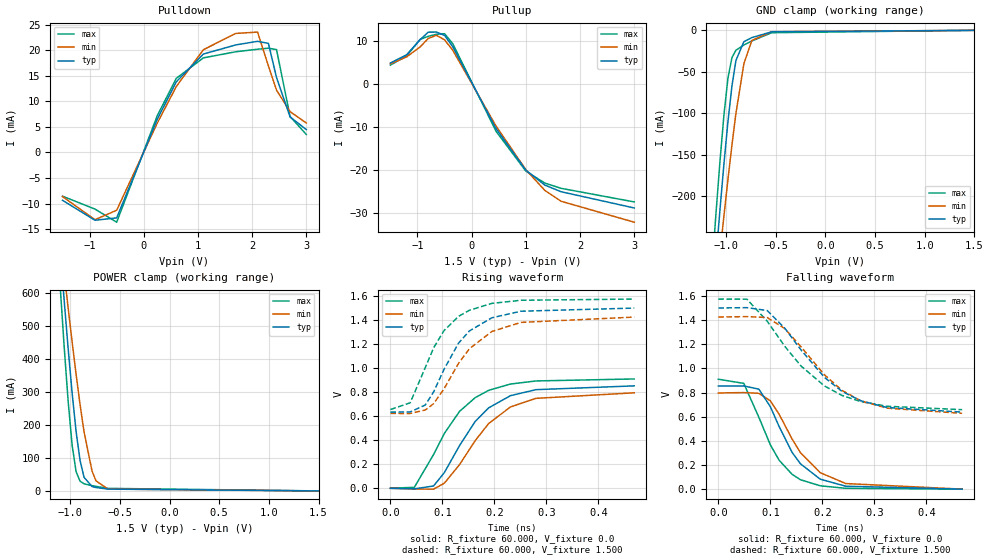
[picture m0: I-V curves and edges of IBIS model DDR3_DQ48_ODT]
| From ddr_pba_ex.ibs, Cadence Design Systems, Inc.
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|   Model DDR3_DQ48_ODT
[Model]   DDR3_DQ48_ODT
Model_type I/O
Polarity   Non-Inverting
Enable   Active-High
Vinl   =   0.575V
Vinh   =   0.925V
C_comp   1.661pF   1.668pF   1.694pF
C_comp_pullup   0.484pF   0.530pF   0.485pF
C_comp_pulldown 1.176pF   1.138pF   1.208pF
[Model Spec]
Vinh   0.925V   NA   NA
Vinl   0.575V   NA   NA
Vmeas   0.750V   NA   NA
[Add Submodel]
|  Submodel_name   Mode
DDR3_DQ_ODT60   Non-Driving
[Temperature Range]   27.000   0.125k   -40.000
[Voltage Range]   1.500V   1.425V   1.575V
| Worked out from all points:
|   slope of the pulldown table from 0 to 0.225 V, typ, clamps not added: 38.1 ohm
|   slope of the pullup table from 0 to 0.225 V, typ, clamps not added: 41.8 ohm
|   GND clamp passes 1 mA (typ) near -0.50 V on its own axis
|   POWER clamp passes 1 mA (typ) near -0.45 V on its own axis
|   rising waveform, R_fixture 60.000, V_fixture 0.0: 20-80 % time 83.7ps typ, 88.3ps min, 82.7ps max; typ from 0 V to 0.853 V
|   rising waveform, R_fixture 60.000, V_fixture 1.500: 20-80 % time 73.2ps typ, 82.3ps min, 66.9ps max; typ from 0.634 V to 1.5 V
|   falling waveform, R_fixture 60.000, V_fixture 0.0: 20-80 % time 66.7ps typ, 73.7ps min, 61ps max; typ from 0.854 V to 0 V
|   falling waveform, R_fixture 60.000, V_fixture 1.500: 20-80 % time 109ps typ, 107ps min, 115ps max; typ from 1.5 V to 0.638 V
[Pulldown]
|Voltage   I(typ)   I(min)   I(max)
-1.5V     -9.367mA   -8.636mA   -8.561mA
-900mV    -13.28mA   -13.17mA   -11.1mA
-500mV    -12.82mA   -11.32mA   -13.66mA
250mV     6.516mA    5.776mA    7.223mA
600mV     13.85mA    12.92mA    14.53mA
1.1V      19.29mA    20.14mA    18.54mA
1.7V      21.08mA    23.33mA    19.74mA
2.1V      21.78mA    23.59mA    20.23mA
2.3V      21.38mA    16.95mA    20.44mA
2.45V     14.67mA    12.22mA    20.16mA
2.7V      6.967mA    7.994mA    7.037mA
3V        4.484mA    5.775mA    3.53mA
[Pullup]
|Voltage   I(typ)   I(min)   I(max)
-1.5V     4.923mA    4.727mA    4.426mA
-1.2V     6.848mA    6.345mA    6.586mA
-950mV    10.37mA    8.696mA    10.41mA
-800mV    12.1mA     10.63mA    11.13mA
-650mV    12.11mA    11.37mA    11.61mA
-500mV    11.33mA    10.3mA     11.74mA
-350mV    8.724mA    7.918mA    9.418mA
450mV     -10.34mA   -9.735mA   -10.95mA
1V        -19.98mA   -19.88mA   -20.21mA
1.35V     -23.45mA   -24.69mA   -22.98mA
1.65V     -24.99mA   -27.21mA   -24.2mA
3V        -28.77mA   -32.07mA   -27.36mA
[GND_clamp]
|Voltage   I(typ)   I(min)   I(max)
-1.5V     -902.4mA   -795.2mA   -923mA
-1.14V    -333.6mA   -361.2mA   -285.4mA
-1.1V     -273.5mA   -314.1mA   -219.4mA
-1.06V    -215.4mA   -267.9mA   -157.1mA
-1.02V    -160.2mA   -222.9mA   -101.2mA
-980mV    -109.7mA   -179.4mA   -57.37mA
-940mV    -66.97mA   -138.2mA   -32.78mA
-900mV    -36.37mA   -100.2mA   -23.99mA
-820mV    -13.67mA   -40.29mA   -17.69mA
-740mV    -8.766mA   -12.21mA   -12.83mA
-540mV    -1.803mA   -1.643mA   -2.86mA
1.5V      1.911nA    275.5nA    464.3pA
[POWER_clamp]
|Voltage   I(typ)   I(min)   I(max)
-1.5V     2.395A     1.917A     2.689A
-1.1V     728.2mA    767.9mA    617.4mA
-1.06V    575.5mA    659.2mA    435.4mA
-1.02V    430.1mA    553.1mA    270.8mA
-980mV    295.8mA    450.4mA    137.9mA
-940mV    179.3mA    352.3mA    58.02mA
-900mV    91.53mA    260.8mA    29.3mA
-860mV    41.11mA    178.7mA    21.47mA
-780mV    13.3mA     60.49mA    15.94mA
-740mV    10.3mA     30.45mA    13.76mA
-620mV    5.486mA    5.676mA    7.71mA
1.5V      -5.523nA   -199nA     -1.165nA
[Ramp]
| variable   typ   min   max
dV/dt_r 0.468/80.625p   0.437/87.256p   0.498/79.888p
dV/dt_f 0.471/0.110n   0.438/0.107n   0.495/0.115n
R_load = 50.000
| The next line is not an IBIS keyword
| [Initial Delay]   0.225ns   0.350ns   0.175ns
[Rising Waveform]
R_fixture= 60.000
V_fixture= 0.0
V_fixture_min= 0.0
V_fixture_max= 0.0
|time   V(typ)   V(min)   V(max)
0s        413.6uV    1.299mV    2.487mV
46ps      -3.618mV   -5.205mV   8.486mV
83ps      20.07mV    -6.362mV   281.6mV
104ps     133mV      44.37mV    458.8mV
133ps     356.3mV    198mV      640.8mV
163ps     556.6mV    396.6mV    754.6mV
189ps     670mV      540mV      815.8mV
231ps     771.7mV    677.7mV    868.2mV
280ps     821.4mV    749.1mV    893.8mV
469ps     852.9mV    795.2mV    910.5mV
[Rising Waveform]
R_fixture= 60.000
V_fixture= 1.500
V_fixture_min= 1.425
V_fixture_max= 1.575
|time   V(typ)   V(min)   V(max)
0s        634.4mV    623.5mV    656.1mV
38ps      636.1mV    623.2mV    711.9mV
67ps      693.8mV    652.2mV    1.004V
83ps      801.3mV    704.5mV    1.168V
103ps     989mV      826.7mV    1.312V
131ps     1.208V     1.04V      1.431V
152ps     1.31V      1.162V     1.482V
195ps     1.419V     1.305V     1.539V
251ps     1.474V     1.381V     1.565V
469ps     1.5V       1.425V     1.575V
[Falling Waveform]
R_fixture= 60.000
V_fixture= 0.0
V_fixture_min= 0.0
V_fixture_max= 0.0
|time   V(typ)   V(min)   V(max)
0s        853.9mV    796.3mV    910.4mV
49ps      854.9mV    800mV      876mV
78ps      828.1mV    793.6mV    595.3mV
100ps     683.6mV    732.1mV    368.2mV
117ps     518.3mV    620mV      239.2mV
142ps     304.1mV    414.4mV    122.8mV
158ps     210.3mV    302.1mV    78.27mV
196ps     82.9mV     136.6mV    27.9mV
245ps     24.45mV    46.73mV    7.37mV
469ps     283.7uV    399.9uV    115.1uV
[Falling Waveform]
R_fixture= 60.000
V_fixture= 1.500
V_fixture_min= 1.425
V_fixture_max= 1.575
|time   V(typ)   V(min)   V(max)
0s        1.5V       1.425V     1.574V
55ps      1.503V     1.429V     1.573V
94ps      1.479V     1.421V     1.391V
128ps     1.332V     1.329V     1.182V
159ps     1.153V     1.179V     1.02V
204ps     926.2mV    947.3mV    855.1mV
238ps     809mV      817.9mV    775.7mV
274ps     732.3mV    731.5mV    725.1mV
324ps     676.5mV    670.8mV    686.7mV
469ps     638mV      627.9mV    658.1mV
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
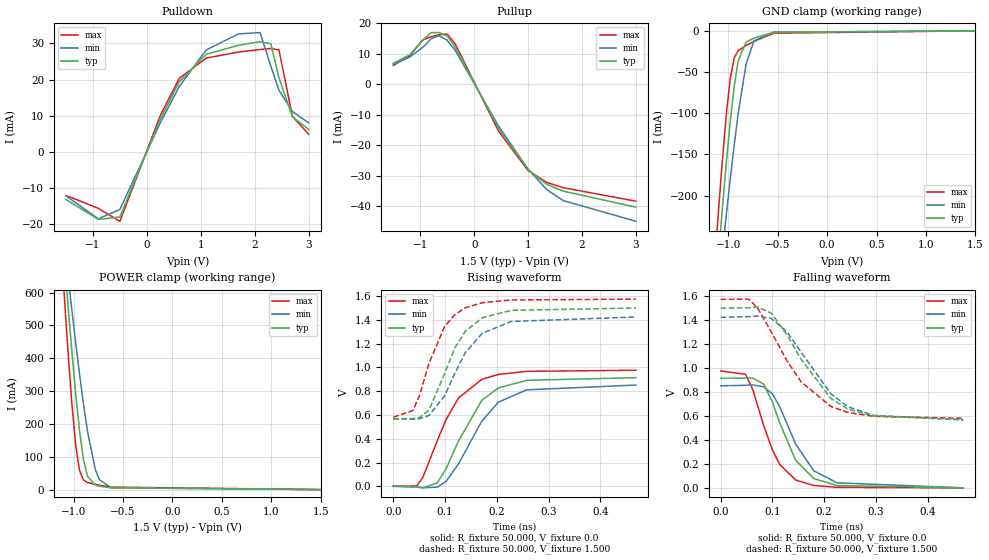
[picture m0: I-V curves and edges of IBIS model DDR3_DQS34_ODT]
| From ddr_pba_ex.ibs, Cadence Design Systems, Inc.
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|   Model DDR3_DQS34_ODT
[Model]   DDR3_DQS34_ODT
Model_type I/O
Polarity   Non-Inverting
Enable   Active-High
Vinl   =   0.575V
Vinh   =   0.925V
C_comp   1.612pF   1.589pF   1.674pF
C_comp_pullup   0.458pF   0.493pF   0.466pF
C_comp_pulldown 1.154pF   1.097pF   1.207pF
[Model Spec]
Vinh   0.925V   NA   NA
Vinl   0.575V   NA   NA
Vmeas   0.750V   NA   NA
[Add Submodel]
|  Submodel_name   Mode
DDR3_DQS_ODT60   Non-Driving
[Temperature Range]   27.000   0.125k   -40.000
[Voltage Range]   1.500V   1.425V   1.575V
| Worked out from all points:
|   slope of the pulldown table from 0 to 0.225 V, typ, clamps not added: 27.2 ohm
|   slope of the pullup table from 0 to 0.225 V, typ, clamps not added: 29.9 ohm
|   GND clamp passes 1 mA (typ) near -0.50 V on its own axis
|   POWER clamp passes 1 mA (typ) near -0.45 V on its own axis
|   rising waveform, R_fixture 50.000, V_fixture 0.0: 20-80 % time 66.9ps typ, 72.5ps min, 64.4ps max; typ from 0 V to 0.915 V
|   rising waveform, R_fixture 50.000, V_fixture 1.500: 20-80 % time 58.4ps typ, 66.4ps min, 52.7ps max; typ from 0.569 V to 1.5 V
|   falling waveform, R_fixture 50.000, V_fixture 0.0: 20-80 % time 53.8ps typ, 60.1ps min, 49ps max; typ from 0.915 V to 0 V
|   falling waveform, R_fixture 50.000, V_fixture 1.500: 20-80 % time 87.5ps typ, 87.7ps min, 90.3ps max; typ from 1.5 V to 0.57 V
[Pulldown]
|Voltage   I(typ)   I(min)   I(max)
-1.5V     -13.11mA   -12.09mA   -11.99mA
-900mV    -18.6mA    -18.43mA   -15.54mA
-500mV    -17.95mA   -15.85mA   -19.12mA
250mV     9.123mA    8.086mA    10.11mA
600mV     19.39mA    18.08mA    20.34mA
1.1V      27mA       28.19mA    25.96mA
1.7V      29.51mA    32.65mA    27.63mA
2.1V      30.49mA    33.01mA    28.32mA
2.3V      29.93mA    23.73mA    28.62mA
2.45V     20.53mA    17.11mA    28.23mA
2.7V      9.751mA    11.19mA    9.851mA
3V        6.277mA    8.093mA    4.942mA
[Pullup]
|Voltage   I(typ)   I(min)   I(max)
-1.5V     6.892mA    6.626mA    6.196mA
-1.2V     9.586mA    8.882mA    9.221mA
-950mV    14.51mA    12.17mA    14.57mA
-800mV    16.94mA    14.89mA    15.59mA
-650mV    16.95mA    15.91mA    16.25mA
-500mV    15.86mA    14.42mA    16.44mA
-350mV    12.21mA    11.08mA    13.19mA
450mV     -14.47mA   -13.63mA   -15.32mA
1V        -27.96mA   -27.83mA   -28.29mA
1.35V     -32.83mA   -34.57mA   -32.17mA
1.65V     -34.98mA   -38.1mA    -33.88mA
3V        -40.28mA   -44.89mA   -38.3mA
[GND_clamp]
|Voltage   I(typ)   I(min)   I(max)
-1.5V     -902.4mA   -795.2mA   -923mA
-1.14V    -333.6mA   -361.2mA   -285.4mA
-1.1V     -273.5mA   -314.1mA   -219.4mA
-1.06V    -215.4mA   -267.9mA   -157.1mA
-1.02V    -160.2mA   -222.9mA   -101.2mA
-980mV    -109.7mA   -179.4mA   -57.37mA
-940mV    -66.97mA   -138.2mA   -32.78mA
-900mV    -36.37mA   -100.2mA   -23.99mA
-820mV    -13.67mA   -40.29mA   -17.69mA
-740mV    -8.766mA   -12.21mA   -12.83mA
-540mV    -1.803mA   -1.643mA   -2.86mA
1.5V      1.904nA    275.5nA    464.3pA
[POWER_clamp]
|Voltage   I(typ)   I(min)   I(max)
-1.5V     2.395A     1.917A     2.689A
-1.1V     728.2mA    767.9mA    617.4mA
-1.06V    575.5mA    659.2mA    435.4mA
-1.02V    430.1mA    553.1mA    270.8mA
-980mV    295.8mA    450.4mA    137.9mA
-940mV    179.3mA    352.3mA    58.02mA
-900mV    91.53mA    260.8mA    29.3mA
-860mV    41.11mA    178.7mA    21.47mA
-780mV    13.3mA     60.49mA    15.94mA
-740mV    10.3mA     30.45mA    13.76mA
-620mV    5.486mA    5.676mA    7.71mA
1.5V      -5.523nA   -199nA     -1.165nA
[Ramp]
| variable   typ   min   max
dV/dt_r 0.549/67.274p   0.512/74.383p   0.586/65.956p
dV/dt_f 0.559/88.706p   0.516/90.109p   0.597/91.626p
R_load = 50.000
| The next line is not an IBIS keyword
| [Initial Delay]   0.225ns   0.350ns   0.175ns
[Rising Waveform]
R_fixture= 50.000
V_fixture= 0.0
V_fixture_min= 0.0
V_fixture_max= 0.0
|time   V(typ)   V(min)   V(max)
0s        454.9uV    1.58mV     3.018mV
45ps      -3.51mV    -5.637mV   3.089mV
57ps      -12.27mV   -12.07mV   74.62mV
85ps      29.19mV    -6.197mV   383.8mV
102ps     148.8mV    41.77mV    562mV
126ps     381.7mV    189.6mV    743.7mV
171ps     723.9mV    548.6mV    899.9mV
203ps     828.2mV    708.2mV    941.9mV
258ps     892.2mV    812.2mV    967.5mV
469ps     914.6mV    852.4mV    976.8mV
[Rising Waveform]
R_fixture= 50.000
V_fixture= 1.500
V_fixture_min= 1.425
V_fixture_max= 1.575
|time   V(typ)   V(min)   V(max)
0s        569.3mV    565.6mV    582mV
38ps      571mV      564.5mV    638.1mV
51ps      580.6mV    569.3mV    770mV
69ps      641.2mV    596.6mV    1.035V
99ps      947.3mV    761.1mV    1.344V
119ps     1.166V     950.8mV    1.445V
139ps     1.304V     1.124V     1.502V
172ps     1.418V     1.288V     1.545V
228ps     1.481V     1.387V     1.568V
469ps     1.5V       1.425V     1.575V
[Falling Waveform]
R_fixture= 50.000
V_fixture= 0.0
V_fixture_min= 0.0
V_fixture_max= 0.0
|time   V(typ)   V(min)   V(max)
0s        914.8mV    852.4mV    976.1mV
48ps      916.2mV    856.6mV    948.7mV
62ps      916.6mV    859.3mV    822mV
83ps      867.7mV    844.5mV    522.2mV
100ps     716.4mV    784.3mV    316.6mV
114ps     543.6mV    679.1mV    195.9mV
145ps     230.1mV    365.4mV    65.5mV
180ps     77.6mV     142.5mV    19.75mV
225ps     19.34mV    42.2mV     4.648mV
469ps     168.9uV    121.2uV    85.85uV
[Falling Waveform]
R_fixture= 50.000
V_fixture= 1.500
V_fixture_min= 1.425
V_fixture_max= 1.575
|time   V(typ)   V(min)   V(max)
0s        1.5V       1.424V     1.574V
54ps      1.504V     1.43V      1.576V
71ps      1.511V     1.435V     1.505V
98ps      1.459V     1.414V     1.3V
129ps     1.273V     1.299V     1.055V
155ps     1.076V     1.136V     888.4mV
213ps     747mV      785.6mV    679.6mV
246ps     657.4mV    677.1mV    629.7mV
295ps     600.2mV    605.8mV    597.9mV
469ps     570mV      567.1mV    580.7mV
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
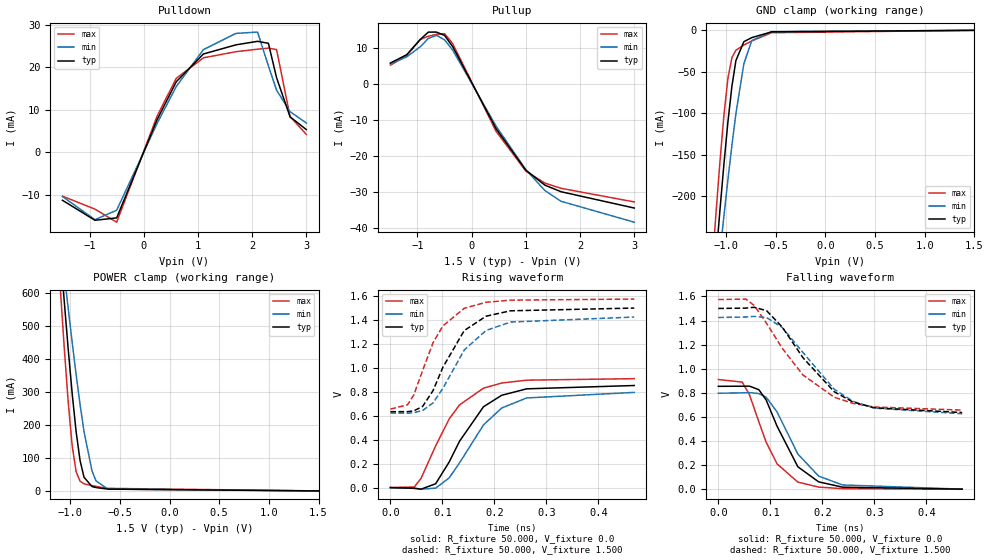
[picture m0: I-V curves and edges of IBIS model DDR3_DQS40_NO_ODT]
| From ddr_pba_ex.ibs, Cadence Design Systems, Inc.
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|   Model DDR3_DQS40_NO_ODT
[Model]   DDR3_DQS40_NO_ODT
Model_type I/O
Polarity   Non-Inverting
Enable   Active-High
Vinl   =   0.703V
Vinh   =   0.796V
C_comp   1.640pF   1.630pF   1.688pF
C_comp_pullup   0.471pF   0.511pF   0.476pF
C_comp_pulldown 1.168pF   1.119pF   1.211pF
[Model Spec]
Vinh   0.796V   NA   NA
Vinl   0.703V   NA   NA
Vmeas   0.750V   NA   NA
[Temperature Range]   27.000   0.125k   -40.000
[Voltage Range]   1.500V   1.425V   1.575V
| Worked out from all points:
|   slope of the pulldown table from 0 to 0.225 V, typ, clamps not added: 31.8 ohm
|   slope of the pullup table from 0 to 0.225 V, typ, clamps not added: 34.8 ohm
|   GND clamp passes 1 mA (typ) near -0.50 V on its own axis
|   POWER clamp passes 1 mA (typ) near -0.45 V on its own axis
|   rising waveform, R_fixture 50.000, V_fixture 0.0: 20-80 % time 73ps typ, 78.2ps min, 70.9ps max; typ from 0 V to 0.853 V
|   rising waveform, R_fixture 50.000, V_fixture 1.500: 20-80 % time 63.7ps typ, 72.4ps min, 57.6ps max; typ from 0.635 V to 1.5 V
|   falling waveform, R_fixture 50.000, V_fixture 0.0: 20-80 % time 58.1ps typ, 64.5ps min, 53.2ps max; typ from 0.854 V to 0 V
|   falling waveform, R_fixture 50.000, V_fixture 1.500: 20-80 % time 97.1ps typ, 96.2ps min, 101ps max; typ from 1.5 V to 0.636 V
[Pulldown]
|Voltage   I(typ)   I(min)   I(max)
-1.5V     -11.24mA   -10.36mA   -10.27mA
-900mV    -15.94mA   -15.8mA    -13.32mA
-500mV    -15.38mA   -13.58mA   -16.39mA
250mV     7.818mA    6.93mA     8.666mA
600mV     16.62mA    15.5mA     17.43mA
1.1V      23.14mA    24.16mA    22.24mA
1.7V      25.29mA    27.98mA    23.68mA
2.1V      26.12mA    28.29mA    24.27mA
2.3V      25.65mA    20.33mA    24.52mA
2.45V     17.59mA    14.66mA    24.19mA
2.7V      8.354mA    9.586mA    8.44mA
3V        5.378mA    6.93mA     4.234mA
[Pullup]
|Voltage   I(typ)   I(min)   I(max)
-1.5V     5.907mA    5.675mA    5.311mA
-1.2V     8.216mA    7.612mA    7.902mA
-950mV    12.44mA    10.43mA    12.49mA
-800mV    14.52mA    12.76mA    13.36mA
-650mV    14.53mA    13.64mA    13.93mA
-500mV    13.59mA    12.36mA    14.09mA
-350mV    10.47mA    9.5mA      11.3mA
450mV     -12.4mA    -11.68mA   -13.13mA
1V        -23.97mA   -23.85mA   -24.24mA
1.35V     -28.14mA   -29.63mA   -27.57mA
1.65V     -29.98mA   -32.65mA   -29.03mA
3V        -34.52mA   -38.47mA   -32.82mA
[GND_clamp]
|Voltage   I(typ)   I(min)   I(max)
-1.5V     -902.4mA   -795.2mA   -923mA
-1.14V    -333.6mA   -361.2mA   -285.4mA
-1.1V     -273.5mA   -314.1mA   -219.4mA
-1.06V    -215.4mA   -267.9mA   -157.1mA
-1.02V    -160.2mA   -222.9mA   -101.2mA
-980mV    -109.7mA   -179.4mA   -57.37mA
-940mV    -66.97mA   -138.2mA   -32.78mA
-900mV    -36.37mA   -100.2mA   -23.99mA
-820mV    -13.67mA   -40.29mA   -17.69mA
-740mV    -8.766mA   -12.21mA   -12.83mA
-540mV    -1.803mA   -1.643mA   -2.86mA
1.5V      1.904nA    275.5nA    464.3pA
[POWER_clamp]
|Voltage   I(typ)   I(min)   I(max)
-1.5V     2.395A     1.917A     2.689A
-1.1V     728.2mA    767.9mA    617.4mA
-1.06V    575.5mA    659.2mA    435.4mA
-1.02V    430.1mA    553.1mA    270.8mA
-980mV    295.8mA    450.4mA    137.9mA
-940mV    179.3mA    352.3mA    58.02mA
-900mV    91.53mA    260.8mA    29.3mA
-860mV    41.11mA    178.7mA    21.47mA
-780mV    13.3mA     60.49mA    15.94mA
-740mV    10.3mA     30.45mA    13.76mA
-620mV    5.486mA    5.676mA    7.71mA
1.5V      -5.523nA   -199nA     -1.165nA
[Ramp]
| variable   typ   min   max
dV/dt_r 0.512/74.400p   0.478/80.454p   0.547/71.752p
dV/dt_f 0.519/99.358p   0.481/97.096p   0.552/0.102n
R_load = 50.000
| The next line is not an IBIS keyword
| [Initial Delay]   0.225ns   0.350ns   0.175ns
[Rising Waveform]
R_fixture= 50.000
V_fixture= 0.0
V_fixture_min= 0.0
V_fixture_max= 0.0
|time   V(typ)   V(min)   V(max)
0s        427.1uV    1.408mV    2.698mV
46ps      -3.782mV   -5.48mV    5.951mV
59ps      -11.88mV   -11.65mV   78.51mV
87ps      33.15mV    -3.69mV    349mV
113ps     214.4mV    82.09mV    573.8mV
133ps     388.4mV    207.7mV    691.8mV
179ps     675.7mV    524.2mV    831mV
214ps     771.7mV    665.3mV    874mV
262ps     825.6mV    749.5mV    898mV
469ps     853.4mV    795.9mV    910.7mV
[Rising Waveform]
R_fixture= 50.000
V_fixture= 1.500
V_fixture_min= 1.425
V_fixture_max= 1.575
|time   V(typ)   V(min)   V(max)
0s        634.5mV    623.6mV    656.4mV
33ps      635.4mV    622.4mV    692.7mV
45ps      641.6mV    626.3mV    774.2mV
62ps      679mV      644.7mV    978.8mV
82ps      810.6mV    708mV      1.21V
101ps     1.006V     829.9mV    1.351V
142ps     1.312V     1.15V      1.498V
184ps     1.432V     1.313V     1.548V
231ps     1.477V     1.383V     1.566V
469ps     1.5V       1.425V     1.575V
[Falling Waveform]
R_fixture= 50.000
V_fixture= 0.0
V_fixture_min= 0.0
V_fixture_max= 0.0
|time   V(typ)   V(min)   V(max)
0s        853.8mV    796.2mV    910.2mV
46ps      854.6mV    799.7mV    888.8mV
60ps      855.2mV    801.8mV    783.3mV
78ps      825.7mV    793.5mV    558.4mV
92ps      740.7mV    763.4mV    391mV
113ps     522.6mV    641.1mV    210mV
153ps     186mV      291.5mV    58.59mV
193ps     60.68mV    108.6mV    17.14mV
239ps     16.65mV    35.02mV    4.345mV
469ps     190.3uV    184.7uV    90.24uV
[Falling Waveform]
R_fixture= 50.000
V_fixture= 1.500
V_fixture_min= 1.425
V_fixture_max= 1.575
|time   V(typ)   V(min)   V(max)
0s        1.5V       1.425V     1.574V
53ps      1.503V     1.429V     1.578V
69ps      1.51V      1.434V     1.525V
93ps      1.481V     1.424V     1.376V
123ps     1.345V     1.342V     1.169V
163ps     1.09V      1.133V     947.2mV
223ps     808.5mV    829.2mV    763mV
259ps     723.1mV    729.4mV    711.6mV
300ps     675.5mV    672.6mV    682.1mV
469ps     636.2mV    626.1mV    656.3mV
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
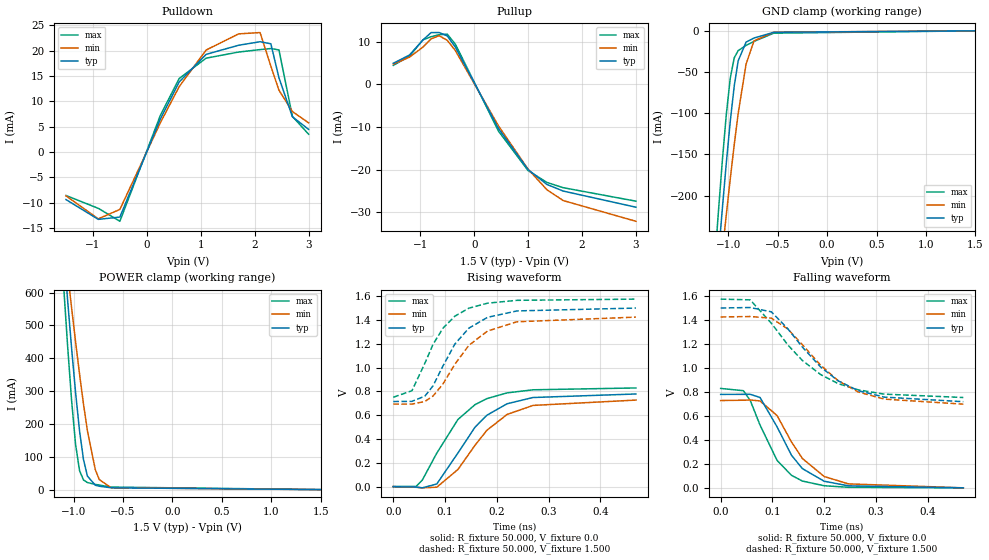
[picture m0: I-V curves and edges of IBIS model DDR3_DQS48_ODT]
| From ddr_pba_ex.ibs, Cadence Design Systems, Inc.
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|   Model DDR3_DQS48_ODT
[Model]   DDR3_DQS48_ODT
Model_type I/O
Polarity   Non-Inverting
Enable   Active-High
Vinl   =   0.703V
Vinh   =   0.796V
C_comp   1.663pF   1.668pF   1.698pF
C_comp_pullup   0.484pF   0.529pF   0.485pF
C_comp_pulldown 1.180pF   1.139pF   1.212pF
[Model Spec]
Vinh   0.796V   NA   NA
Vinl   0.703V   NA   NA
Vmeas   0.750V   NA   NA
[Add Submodel]
|  Submodel_name   Mode
DDR3_DQS_ODT60   Non-Driving
[Temperature Range]   27.000   0.125k   -40.000
[Voltage Range]   1.500V   1.425V   1.575V
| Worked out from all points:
|   slope of the pulldown table from 0 to 0.225 V, typ, clamps not added: 38.1 ohm
|   slope of the pullup table from 0 to 0.225 V, typ, clamps not added: 41.8 ohm
|   GND clamp passes 1 mA (typ) near -0.50 V on its own axis
|   POWER clamp passes 1 mA (typ) near -0.45 V on its own axis
|   rising waveform, R_fixture 50.000, V_fixture 0.0: 20-80 % time 80.4ps typ, 85.2ps min, 78.7ps max; typ from 0 V to 0.779 V
|   rising waveform, R_fixture 50.000, V_fixture 1.500: 20-80 % time 69.3ps typ, 78.4ps min, 63ps max; typ from 0.715 V to 1.5 V
|   falling waveform, R_fixture 50.000, V_fixture 0.0: 20-80 % time 62.4ps typ, 69.3ps min, 57.2ps max; typ from 0.779 V to 0 V
|   falling waveform, R_fixture 50.000, V_fixture 1.500: 20-80 % time 107ps typ, 105ps min, 112ps max; typ from 1.5 V to 0.719 V
[Pulldown]
|Voltage   I(typ)   I(min)   I(max)
-1.5V     -9.367mA   -8.636mA   -8.561mA
-900mV    -13.28mA   -13.17mA   -11.1mA
-500mV    -12.82mA   -11.32mA   -13.66mA
250mV     6.516mA    5.776mA    7.223mA
600mV     13.85mA    12.92mA    14.53mA
1.1V      19.29mA    20.14mA    18.54mA
1.7V      21.08mA    23.33mA    19.74mA
2.1V      21.78mA    23.59mA    20.23mA
2.3V      21.38mA    16.95mA    20.44mA
2.45V     14.67mA    12.22mA    20.16mA
2.7V      6.967mA    7.994mA    7.037mA
3V        4.485mA    5.775mA    3.53mA
[Pullup]
|Voltage   I(typ)   I(min)   I(max)
-1.5V     4.923mA    4.727mA    4.426mA
-1.2V     6.848mA    6.345mA    6.586mA
-950mV    10.37mA    8.696mA    10.41mA
-800mV    12.1mA     10.63mA    11.13mA
-650mV    12.11mA    11.37mA    11.61mA
-500mV    11.33mA    10.3mA     11.74mA
-350mV    8.724mA    7.918mA    9.418mA
450mV     -10.34mA   -9.735mA   -10.95mA
1V        -19.98mA   -19.88mA   -20.21mA
1.35V     -23.45mA   -24.69mA   -22.98mA
1.65V     -24.99mA   -27.21mA   -24.2mA
3V        -28.77mA   -32.07mA   -27.36mA
[GND_clamp]
|Voltage   I(typ)   I(min)   I(max)
-1.5V     -902.4mA   -795.2mA   -923mA
-1.14V    -333.6mA   -361.2mA   -285.4mA
-1.1V     -273.5mA   -314.1mA   -219.4mA
-1.06V    -215.4mA   -267.9mA   -157.1mA
-1.02V    -160.2mA   -222.9mA   -101.2mA
-980mV    -109.7mA   -179.4mA   -57.37mA
-940mV    -66.97mA   -138.2mA   -32.78mA
-900mV    -36.37mA   -100.2mA   -23.99mA
-820mV    -13.67mA   -40.29mA   -17.69mA
-740mV    -8.766mA   -12.21mA   -12.83mA
-540mV    -1.803mA   -1.643mA   -2.86mA
1.5V      1.904nA    275.5nA    464.3pA
[POWER_clamp]
|Voltage   I(typ)   I(min)   I(max)
-1.5V     2.395A     1.917A     2.689A
-1.1V     728.2mA    767.9mA    617.4mA
-1.06V    575.5mA    659.2mA    435.4mA
-1.02V    430.1mA    553.1mA    270.8mA
-980mV    295.8mA    450.4mA    137.9mA
-940mV    179.3mA    352.3mA    58.02mA
-900mV    91.53mA    260.8mA    29.3mA
-860mV    41.11mA    178.7mA    21.47mA
-780mV    13.3mA     60.49mA    15.94mA
-740mV    10.3mA     30.45mA    13.76mA
-620mV    5.486mA    5.676mA    7.71mA
1.5V      -5.523nA   -199nA     -1.165nA
[Ramp]
| variable   typ   min   max
dV/dt_r 0.468/80.639p   0.437/85.630p   0.498/79.331p
dV/dt_f 0.471/0.110n   0.438/0.106n   0.495/0.113n
R_load = 50.000
| The next line is not an IBIS keyword
| [Initial Delay]   0.225ns   0.350ns   0.175ns
[Rising Waveform]
R_fixture= 50.000
V_fixture= 0.0
V_fixture_min= 0.0
V_fixture_max= 0.0
|time   V(typ)   V(min)   V(max)
0s        397.8uV    1.28mV     2.448mV
44ps      -2.508mV   -4.35mV    2.872mV
56ps      -9.045mV   -9.242mV   55.79mV
84ps      23.3mV     -3.631mV   282.2mV
125ps     284mV      145.5mV    565.1mV
158ps     500.6mV    348.6mV    689.4mV
181ps     600.9mV    474.6mV    740.1mV
220ps     696.9mV    607.1mV    788.2mV
270ps     749.1mV    682.8mV    813.9mV
469ps     778.8mV    727.6mV    829.4mV
[Rising Waveform]
R_fixture= 50.000
V_fixture= 1.500
V_fixture_min= 1.425
V_fixture_max= 1.575
|time   V(typ)   V(min)   V(max)
0s        715.5mV    694.2mV    751.5mV
36ps      716.8mV    693.9mV    806mV
61ps      760.4mV    716mV      1.037V
77ps      848.3mV    762.5mV    1.197V
96ps      1.014V     863.1mV    1.331V
119ps     1.198V     1.029V     1.432V
146ps     1.331V     1.187V     1.499V
182ps     1.422V     1.307V     1.541V
239ps     1.476V     1.385V     1.565V
469ps     1.5V       1.424V     1.575V
[Falling Waveform]
R_fixture= 50.000
V_fixture= 0.0
V_fixture_min= 0.0
V_fixture_max= 0.0
|time   V(typ)   V(min)   V(max)
0s        779.5mV    728.3mV    829.2mV
44ps      780mV      731.1mV    810.3mV
57ps      780.3mV    732.8mV    729.8mV
76ps      754.3mV    725mV      524.7mV
109ps     509mV      603mV      229.2mV
137ps     271.2mV    382mV      104.3mV
158ps     160.5mV    245mV      56.81mV
200ps     55.46mV    95.01mV    17.78mV
247ps     16.87mV    33.17mV    4.943mV
469ps     224.9uV    291.8uV    96.47uV
[Falling Waveform]
R_fixture= 50.000
V_fixture= 1.500
V_fixture_min= 1.425
V_fixture_max= 1.575
|time   V(typ)   V(min)   V(max)
0s        1.5V       1.425V     1.574V
57ps      1.504V     1.429V     1.568V
98ps      1.468V     1.415V     1.373V
130ps     1.326V     1.324V     1.191V
158ps     1.174V     1.194V     1.062V
193ps     1.009V     1.024V     945.6mV
227ps     892.9mV    893.8mV    869.5mV
266ps     810.4mV    799.6mV    817.5mV
316ps     756.9mV    740.2mV    781.7mV
469ps     718.6mV    698.2mV    753.6mV
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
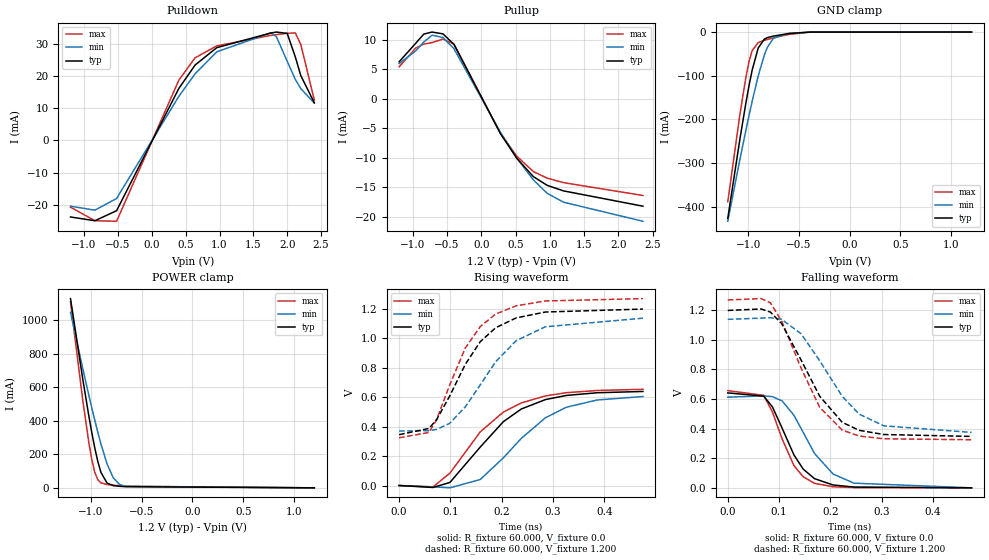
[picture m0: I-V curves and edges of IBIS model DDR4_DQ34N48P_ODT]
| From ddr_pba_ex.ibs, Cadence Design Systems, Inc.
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|   Model DDR4_DQ34N48P_ODT
[Model]   DDR4_DQ34N48P_ODT
Model_type I/O
Polarity   Non-Inverting
Enable   Active-High
Vinl =  0.823V
Vinh =  0.887V
C_comp   1.689pF   1.691pF   1.711pF
C_comp_pullup   0.525pF   0.576pF   0.518pF
C_comp_pulldown   1.164pF   1.114pF   1.192pF
[Model Spec]
Vinh   0.887V   NA   NA
Vinl   0.823V   NA   NA
Vmeas   0.840V   NA   NA
[Add Submodel]
|  Submodel_name   Mode
DDR4_DQ_ODT60   Non-Driving
[Temperature Range]   27.000   0.125k   -40.000
[Voltage Range]   1.200V   1.140V   1.270V
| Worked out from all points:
|   slope of the pulldown table from 0 to 0.18 V, typ, clamps not added: 23.3 ohm
|   slope of the pullup table from 0 to 0.18 V, typ, clamps not added: 45.9 ohm
|   GND clamp passes 1 mA (typ) near -0.50 V on its own axis
|   POWER clamp passes 1 mA (typ) near -0.46 V on its own axis
|   rising waveform, R_fixture 60.000, V_fixture 0.0: 20-80 % time 105ps typ, 111ps min, 106ps max; typ from 0.002 V to 0.64 V
|   rising waveform, R_fixture 60.000, V_fixture 1.200: 20-80 % time 87.2ps typ, 101ps min, 77.5ps max; typ from 0.346 V to 1.2 V
|   falling waveform, R_fixture 60.000, V_fixture 0.0: 20-80 % time 54.7ps typ, 65.3ps min, 47.2ps max; typ from 0.642 V to 0 V
|   falling waveform, R_fixture 60.000, V_fixture 1.200: 20-80 % time 80.4ps typ, 90.4ps min, 73.9ps max; typ from 1.2 V to 0.348 V
[Pulldown]
|Voltage   I(typ)   I(min)   I(max)
-1.2V     -23.72mA   -20.38mA   -20.68mA
-840mV    -24.88mA   -21.61mA   -24.88mA
-520mV    -21.78mA   -18mA      -25.05mA
400mV     16.1mA     13.66mA    18.67mA
640mV     23.35mA    20.64mA    25.58mA
960mV     28.73mA    27.44mA    29.28mA
1.76V     33.27mA    33.33mA    32.54mA
1.84V     33.56mA    32.14mA    32.76mA
2V        33.13mA    24.48mA    33.18mA
2.12V     25.82mA    18.86mA    33.28mA
2.2V      20.09mA    16.05mA    29.74mA
2.4V      11.64mA    11.56mA    12.48mA
[Pullup]
|Voltage   I(typ)   I(min)   I(max)
-1.2V     6.276mA    5.968mA    5.424mA
-960mV    9.396mA    8.108mA    8.597mA
-840mV    10.98mA    9.634mA    9.283mA
-720mV    11.33mA    10.8mA     9.54mA
-560mV    11.02mA    10.4mA     10.13mA
-400mV    9.244mA    8.51mA     9.292mA
280mV     -5.933mA   -5.721mA   -5.889mA
520mV     -10.14mA   -10.1mA    -9.786mA
760mV     -13.22mA   -13.77mA   -12.36mA
960mV     -14.69mA   -16.04mA   -13.47mA
1.2V      -15.64mA   -17.56mA   -14.24mA
2.36V     -18.24mA   -20.8mA    -16.42mA
[GND_clamp]
|Voltage   I(typ)   I(min)   I(max)
-1.2V     -426.2mA   -432.8mA   -388.3mA
-1.08V    -244.1mA   -290.9mA   -187.6mA
-1.02V    -160.2mA   -222.9mA   -101.2mA
-990mV    -121.8mA   -190.1mA   -66.76mA
-960mV    -87.12mA   -158.5mA   -42.47mA
-900mV    -36.37mA   -100.2mA   -23.99mA
-840mV    -16.17mA   -52.6mA    -18.98mA
-810mV    -12.75mA   -34.94mA   -17.06mA
-750mV    -9.219mA   -14.09mA   -13.42mA
-600mV    -3.476mA   -2.979mA   -5.372mA
-390mV    -77.95uA   -145.6uA   -88.64uA
1.2V      1.573nA    185.8nA    251.5pA
[POWER_clamp]
|Voltage   I(typ)   I(min)   I(max)
-1.2V     1.129A     1.047A     1.109A
-1.08V    651.1mA    713.3mA    524.8mA
-1.02V    430.1mA    553.1mA    270.8mA
-990mV    328mA      475.7mA    167mA
-960mV    234.7mA    400.6mA    90.32mA
-930mV    154.2mA    328.7mA    47.17mA
-900mV    91.53mA    260.8mA    29.3mA
-840mV    28.2mA     142.5mA    19.67mA
-780mV    13.3mA     60.49mA    15.94mA
-720mV    9.309mA    21.57mA    12.7mA
-660mV    6.902mA    8.818mA    9.642mA
1.2V      -4.11nA    -153.5nA   -872pA
[Ramp]
| variable   typ   min   max
dV/dt_r 0.348/0.102n   0.332/0.111n   0.351/0.102n
dV/dt_f 0.481/82.840p   0.430/93.487p   0.535/75.995p
R_load = 50.000
| The next line is not an IBIS keyword
| [Initial Delay]   0.325ns   0.500ns   0.200ns
[Rising Waveform]
R_fixture= 60.000
V_fixture= 0.0
V_fixture_min= 0.0
V_fixture_max= 0.0
|time   V(typ)   V(min)   V(max)
0s        1.745mV    1.208mV    364.9uV
66ps      -11.98mV   -7.582mV   -8.093mV
99ps      22.37mV    -14.41mV   85.62mV
158ps     262.2mV    42.12mV    365.4mV
203ps     434.6mV    189.1mV    499.9mV
238ps     520.7mV    321.3mV    561.8mV
285ps     584.6mV    461.1mV    609.5mV
326ps     612.8mV    532.8mV    631.4mV
386ps     631.1mV    582mV      646.6mV
475ps     639.7mV    605.5mV    654.3mV
[Rising Waveform]
R_fixture= 60.000
V_fixture= 1.200
V_fixture_min= 1.140
V_fixture_max= 1.270
|time   V(typ)   V(min)   V(max)
0s        346.5mV    371.3mV    325.1mV
58ps      388.6mV    372.9mV    361.5mV
73ps      448.3mV    382.4mV    448.5mV
98ps      605.5mV    421.9mV    679.6mV
129ps     824.2mV    535.4mV    935mV
158ps     977.3mV    684.2mV    1.08V
188ps     1.072V     841.4mV    1.165V
228ps     1.139V     984.2mV    1.221V
285ps     1.179V     1.079V     1.254V
475ps     1.199V     1.137V     1.27V
[Falling Waveform]
R_fixture= 60.000
V_fixture= 0.0
V_fixture_min= 0.0
V_fixture_max= 0.0
|time   V(typ)   V(min)   V(max)
0s        641.7mV    612.7mV    657mV
70ps      619.8mV    621.1mV    625.2mV
87ps      547.4mV    616.5mV    513mV
106ps     402.6mV    587.2mV    330.1mV
129ps     222mV      490mV      149.7mV
147ps     126.5mV    374.6mV    74.89mV
169ps     62.17mV    232.6mV    30.41mV
205ps     19.52mV    93.62mV    7.468mV
246ps     5.364mV    31.59mV    1.875mV
475ps     129.2uV    183.3uV    57.78uV
[Falling Waveform]
R_fixture= 60.000
V_fixture= 1.200
V_fixture_min= 1.140
V_fixture_max= 1.270
|time   V(typ)   V(min)   V(max)
0s        1.199V     1.139V     1.27V
65ps      1.209V     1.147V     1.279V
83ps      1.188V     1.15V      1.251V
105ps     1.11V      1.139V     1.127V
143ps     862.9mV    1.041V     808.4mV
179ps     619.8mV    859.7mV    544.6mV
223ps     442.9mV    618.4mV    390.2mV
256ps     388.8mV    498.1mV    350.1mV
304ps     360.4mV    419.2mV    331.5mV
475ps     347.6mV    374.6mV    325.1mV
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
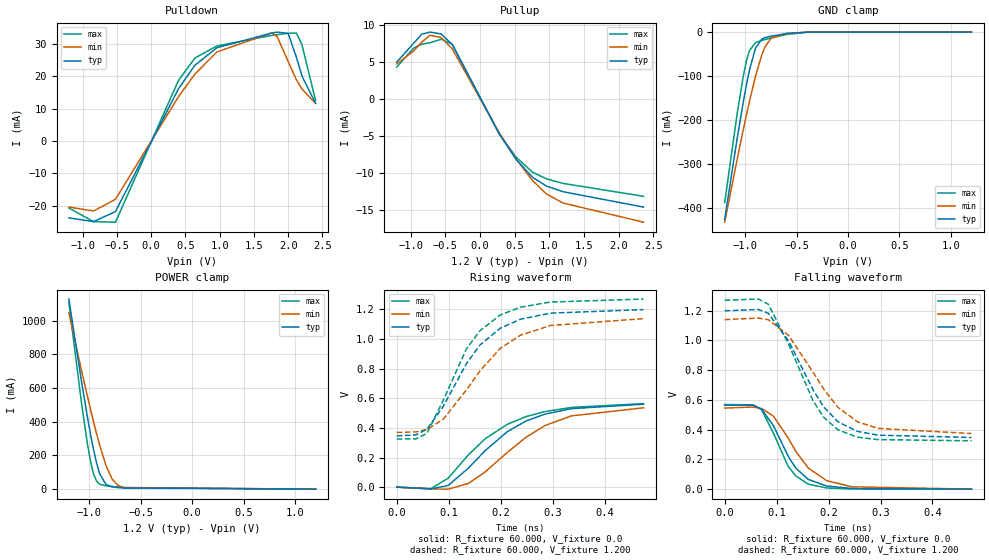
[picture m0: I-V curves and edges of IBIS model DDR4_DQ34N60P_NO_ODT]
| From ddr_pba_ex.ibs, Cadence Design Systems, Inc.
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|   Model DDR4_DQ34N60P_NO_ODT
[Model]   DDR4_DQ34N60P_NO_ODT
Model_type I/O
Polarity   Non-Inverting
Enable   Active-High
Vinl   =  823550V
Vinh   =  887750V
C_comp   1.703pF   1.712pF   1.718pF
C_comp_pullup   0.536pF   0.593pF   0.524pF
C_comp_pulldown 1.166pF   1.119pF   1.193pF
[Model Spec]
Vinh   0.887V   NA   NA
Vinl   0.823V   NA   NA
Vmeas   0.840V   NA   NA
[Temperature Range]   27.000   0.125k   -40.000
[Voltage Range]   1.200V   1.140V   1.270V
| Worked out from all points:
|   slope of the pulldown table from 0 to 0.18 V, typ, clamps not added: 23.3 ohm
|   slope of the pullup table from 0 to 0.18 V, typ, clamps not added: 57.4 ohm
|   GND clamp passes 1 mA (typ) near -0.50 V on its own axis
|   POWER clamp passes 1 mA (typ) near -0.46 V on its own axis
|   rising waveform, R_fixture 60.000, V_fixture 0.0: 20-80 % time 116ps typ, 122ps min, 118ps max; typ from 0.001 V to 0.56 V
|   rising waveform, R_fixture 60.000, V_fixture 1.200: 20-80 % time 95.8ps typ, 111ps min, 86.1ps max; typ from 0.346 V to 1.2 V
|   falling waveform, R_fixture 60.000, V_fixture 0.0: 20-80 % time 54.2ps typ, 65.2ps min, 45.8ps max; typ from 0.565 V to 0 V
|   falling waveform, R_fixture 60.000, V_fixture 1.200: 20-80 % time 80.7ps typ, 90.9ps min, 74.1ps max; typ from 1.2 V to 0.348 V
[Pulldown]
|Voltage   I(typ)   I(min)   I(max)
-1.2V     -23.72mA   -20.38mA   -20.68mA
-840mV    -24.88mA   -21.61mA   -24.88mA
-520mV    -21.78mA   -18mA      -25.05mA
400mV     16.1mA     13.66mA    18.67mA
640mV     23.35mA    20.64mA    25.58mA
960mV     28.73mA    27.44mA    29.28mA
1.76V     33.27mA    33.33mA    32.54mA
1.84V     33.56mA    32.14mA    32.76mA
2V        33.13mA    24.48mA    33.18mA
2.12V     25.82mA    18.86mA    33.28mA
2.2V      20.09mA    16.05mA    29.74mA
2.4V      11.64mA    11.56mA    12.48mA
[Pullup]
|Voltage   I(typ)   I(min)   I(max)
-1.2V     5.02mA     4.773mA    4.338mA
-960mV    7.516mA    6.485mA    6.876mA
-840mV    8.783mA    7.706mA    7.425mA
-720mV    9.066mA    8.641mA    7.63mA
-560mV    8.818mA    8.321mA    8.099mA
-400mV    7.394mA    6.807mA    7.432mA
280mV     -4.745mA   -4.576mA   -4.71mA
520mV     -8.111mA   -8.075mA   -7.827mA
760mV     -10.57mA   -11.01mA   -9.882mA
960mV     -11.75mA   -12.82mA   -10.77mA
1.2V      -12.51mA   -14.04mA   -11.39mA
2.36V     -14.59mA   -16.63mA   -13.13mA
[GND_clamp]
|Voltage   I(typ)   I(min)   I(max)
-1.2V     -426.2mA   -432.8mA   -388.3mA
-1.08V    -244.1mA   -290.9mA   -187.6mA
-1.02V    -160.2mA   -222.9mA   -101.2mA
-990mV    -121.8mA   -190.1mA   -66.76mA
-960mV    -87.12mA   -158.5mA   -42.47mA
-900mV    -36.37mA   -100.2mA   -23.99mA
-840mV    -16.17mA   -52.6mA    -18.98mA
-810mV    -12.75mA   -34.94mA   -17.06mA
-750mV    -9.219mA   -14.09mA   -13.42mA
-600mV    -3.476mA   -2.979mA   -5.372mA
-390mV    -77.95uA   -145.6uA   -88.64uA
1.2V      1.573nA    185.8nA    251.5pA
[POWER_clamp]
|Voltage   I(typ)   I(min)   I(max)
-1.2V     1.129A     1.047A     1.109A
-1.08V    651.1mA    713.3mA    524.8mA
-1.02V    430.1mA    553.1mA    270.8mA
-990mV    328mA      475.7mA    167mA
-960mV    234.7mA    400.6mA    90.32mA
-930mV    154.2mA    328.7mA    47.17mA
-900mV    91.53mA    260.8mA    29.3mA
-840mV    28.2mA     142.5mA    19.67mA
-780mV    13.3mA     60.49mA    15.94mA
-720mV    9.309mA    21.57mA    12.7mA
-660mV    6.902mA    8.818mA    9.642mA
1.2V      -4.11nA    -153.5nA   -872pA
[Ramp]
| variable   typ   min   max
dV/dt_r 0.301/0.113n   0.290/0.120n   0.299/0.111n
dV/dt_f 0.481/82.284p   0.430/94.734p   0.535/76.742p
R_load = 50.000
| The next line is not an IBIS keyword
| [Initial Delay]   0.325ns   0.520ns   0.200ns
[Rising Waveform]
R_fixture= 60.000
V_fixture= 0.0
V_fixture_min= 0.0
V_fixture_max= 0.0
|time   V(typ)   V(min)   V(max)
0s        1.472mV    660.6uV    338.7uV
66ps      -11.39mV   -11.28mV   -9.106mV
99ps      12.2mV     -12.89mV   61.27mV
138ps     129.2mV    25.84mV    218.9mV
170ps     246.7mV    103mV      326.5mV
213ps     375.2mV    235.5mV    424.8mV
249ps     447.3mV    338mV      476.5mV
286ps     493.9mV    417.1mV    511.1mV
336ps     529.9mV    481mV      538.3mV
475ps     560.2mV    535.7mV    563.9mV
[Rising Waveform]
R_fixture= 60.000
V_fixture= 1.200
V_fixture_min= 1.140
V_fixture_max= 1.270
|time   V(typ)   V(min)   V(max)
0s        346.1mV    369.6mV    325.1mV
37ps      353.4mV    373.4mV    326.6mV
58ps      391.2mV    388.8mV    363.3mV
89ps      542.9mV    457.3mV    583.1mV
134ps     832.4mV    655.4mV    932.3mV
160ps     958.8mV    784.1mV    1.055V
199ps     1.072V     936.2mV    1.161V
238ps     1.133V     1.025V     1.214V
296ps     1.174V     1.091V     1.249V
475ps     1.198V     1.137V     1.269V
[Falling Waveform]
R_fixture= 60.000
V_fixture= 0.0
V_fixture_min= 0.0
V_fixture_max= 0.0
|time   V(typ)   V(min)   V(max)
0s        564.6mV    545.3mV    569mV
54ps      565.8mV    552.1mV    567.4mV
71ps      538.5mV    542.6mV    534.5mV
94ps      425.4mV    490.5mV    375mV
122ps     223.1mV    345mV      154.1mV
137ps     140.9mV    254.4mV    88.68mV
161ps     65.71mV    142.2mV    33.27mV
196ps     21.33mV    57.53mV    8.435mV
245ps     4.537mV    15.89mV    1.576mV
475ps     107.8uV    117.5uV    48.05uV
[Falling Waveform]
R_fixture= 60.000
V_fixture= 1.200
V_fixture_min= 1.140
V_fixture_max= 1.270
|time   V(typ)   V(min)   V(max)
0s        1.199V     1.14V      1.27V
65ps      1.208V     1.15V      1.278V
84ps      1.182V     1.139V     1.243V
123ps     995.7mV    1.034V     974.7mV
170ps     668.2mV    787mV      595.7mV
191ps     551.5mV    670.7mV    481.8mV
218ps     453mV      550.1mV    399mV
256ps     387.8mV    452.5mV    349.5mV
295ps     363.2mV    408.7mV    333.1mV
475ps     347.6mV    374mV      325.1mV
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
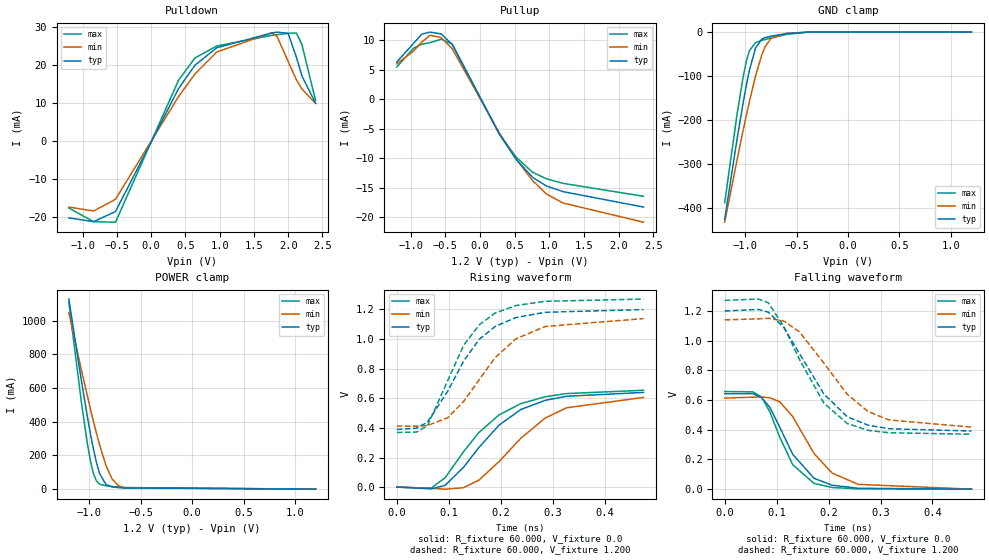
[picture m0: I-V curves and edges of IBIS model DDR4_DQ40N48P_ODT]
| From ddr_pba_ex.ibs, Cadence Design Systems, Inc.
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|   Model DDR4_DQ40N48P_ODT
[Model]   DDR4_DQ40N48P_ODT
Model_type I/O
Polarity   Non-Inverting
Enable   Active-High
Vinl =  0.823V
Vinh =  0.887V
C_comp   1.702pF   1.710pF   1.717pF
C_comp_pullup   0.526pF   0.578pF   0.518pF
C_comp_pulldown   1.175pF   1.131pF   1.198pF
[Model Spec]
Vinh   0.887V   NA   NA
Vinl   0.823V   NA   NA
Vmeas   0.840V   NA   NA
[Add Submodel]
|  Submodel_name   Mode
DDR4_DQ_ODT60   Non-Driving
[Temperature Range]   27.000   0.125k   -40.000
[Voltage Range]   1.200V   1.140V   1.270V
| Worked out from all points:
|   slope of the pulldown table from 0 to 0.18 V, typ, clamps not added: 27.2 ohm
|   slope of the pullup table from 0 to 0.18 V, typ, clamps not added: 45.9 ohm
|   GND clamp passes 1 mA (typ) near -0.50 V on its own axis
|   POWER clamp passes 1 mA (typ) near -0.46 V on its own axis
|   rising waveform, R_fixture 60.000, V_fixture 0.0: 20-80 % time 105ps typ, 112ps min, 106ps max; typ from 0.002 V to 0.64 V
|   rising waveform, R_fixture 60.000, V_fixture 1.200: 20-80 % time 87.3ps typ, 102ps min, 77.7ps max; typ from 0.389 V to 1.2 V
|   falling waveform, R_fixture 60.000, V_fixture 0.0: 20-80 % time 60ps typ, 71ps min, 51.7ps max; typ from 0.642 V to 0 V
|   falling waveform, R_fixture 60.000, V_fixture 1.200: 20-80 % time 89ps typ, 99ps min, 83.3ps max; typ from 1.2 V to 0.391 V
[Pulldown]
|Voltage   I(typ)   I(min)   I(max)
-1.2V     -20.33mA   -17.47mA   -17.73mA
-840mV    -21.33mA   -18.52mA   -21.33mA
-520mV    -18.67mA   -15.43mA   -21.47mA
400mV     13.8mA     11.7mA     16mA
640mV     20.01mA    17.69mA    21.92mA
960mV     24.62mA    23.51mA    25.09mA
1.76V     28.51mA    28.56mA    27.88mA
1.84V     28.75mA    27.53mA    28.07mA
2V        28.39mA    20.97mA    28.43mA
2.12V     22.12mA    16.15mA    28.51mA
2.2V      17.21mA    13.75mA    25.48mA
2.4V      9.967mA    9.905mA    10.69mA
[Pullup]
|Voltage   I(typ)   I(min)   I(max)
-1.2V     6.276mA    5.968mA    5.424mA
-960mV    9.396mA    8.108mA    8.597mA
-840mV    10.98mA    9.634mA    9.283mA
-720mV    11.33mA    10.8mA     9.54mA
-560mV    11.02mA    10.4mA     10.13mA
-400mV    9.244mA    8.51mA     9.292mA
280mV     -5.933mA   -5.721mA   -5.889mA
520mV     -10.14mA   -10.1mA    -9.786mA
760mV     -13.22mA   -13.77mA   -12.36mA
960mV     -14.69mA   -16.04mA   -13.47mA
1.2V      -15.64mA   -17.56mA   -14.24mA
2.36V     -18.24mA   -20.8mA    -16.42mA
[GND_clamp]
|Voltage   I(typ)   I(min)   I(max)
-1.2V     -426.2mA   -432.8mA   -388.3mA
-1.08V    -244.1mA   -290.9mA   -187.6mA
-1.02V    -160.2mA   -222.9mA   -101.2mA
-990mV    -121.8mA   -190.1mA   -66.76mA
-960mV    -87.12mA   -158.5mA   -42.47mA
-900mV    -36.37mA   -100.2mA   -23.99mA
-840mV    -16.17mA   -52.6mA    -18.98mA
-810mV    -12.75mA   -34.94mA   -17.06mA
-750mV    -9.219mA   -14.09mA   -13.42mA
-600mV    -3.476mA   -2.979mA   -5.372mA
-390mV    -77.95uA   -145.6uA   -88.64uA
1.2V      1.573nA    185.8nA    251.5pA
[POWER_clamp]
|Voltage   I(typ)   I(min)   I(max)
-1.2V     1.129A     1.047A     1.109A
-1.08V    651.1mA    713.3mA    524.8mA
-1.02V    430.1mA    553.1mA    270.8mA
-990mV    328mA      475.7mA    167mA
-960mV    234.7mA    400.6mA    90.32mA
-930mV    154.2mA    328.7mA    47.17mA
-900mV    91.53mA    260.8mA    29.3mA
-840mV    28.2mA     142.5mA    19.67mA
-780mV    13.3mA     60.49mA    15.94mA
-720mV    9.309mA    21.57mA    12.7mA
-660mV    6.902mA    8.818mA    9.642mA
1.2V      -4.11nA    -153.5nA   -872pA
[Ramp]
| variable   typ   min   max
dV/dt_r 0.348/0.102n   0.332/0.114n   0.351/0.102n
dV/dt_f 0.453/90.927p   0.403/0.102n   0.505/84.594p
R_load = 50.000
| The next line is not an IBIS keyword
| [Initial Delay]   0.325ns   0.500ns   0.200ns
[Rising Waveform]
R_fixture= 60.000
V_fixture= 0.0
V_fixture_min= 0.0
V_fixture_max= 0.0
|time   V(typ)   V(min)   V(max)
0s        1.734mV    1.183mV    369.4uV
66ps      -11.5mV    -7.311mV   -6.758mV
93ps      12.59mV    -13.14mV   63.77mV
128ps     132.4mV    -3.652mV   237mV
158ps     267.7mV    47.24mV    368.9mV
197ps     419.4mV    173.5mV    488.3mV
239ps     525.1mV    331.3mV    564.4mV
286ps     586.7mV    467.5mV    610.9mV
327ps     613.9mV    536.3mV    632.1mV
475ps     639.8mV    605.8mV    654.4mV
[Rising Waveform]
R_fixture= 60.000
V_fixture= 1.200
V_fixture_min= 1.140
V_fixture_max= 1.270
|time   V(typ)   V(min)   V(max)
0s        389.3mV    413.1mV    369.6mV
38ps      398.1mV    411.4mV    372.3mV
59ps      439.4mV    416.3mV    414.5mV
98ps      647.3mV    468.8mV    719.4mV
129ps     853.7mV    580.5mV    959.4mV
159ps     998.8mV    727.9mV    1.097V
189ps     1.084V     873.5mV    1.175V
229ps     1.145V     1.001V     1.226V
286ps     1.181V     1.085V     1.255V
475ps     1.199V     1.138V     1.27V
[Falling Waveform]
R_fixture= 60.000
V_fixture= 0.0
V_fixture_min= 0.0
V_fixture_max= 0.0
|time   V(typ)   V(min)   V(max)
0s        641.8mV    612.8mV    657mV
54ps      642.5mV    618.8mV    654.7mV
71ps      616.3mV    619.9mV    620.4mV
87ps      550.6mV    615.1mV    519.4mV
106ps     416.9mV    587.8mV    350.2mV
131ps     234.1mV    488mV      164.4mV
172ps     73.34mV    239.4mV    38.63mV
207ps     26.56mV    108mV      11.27mV
257ps     6.279mV    32.47mV    2.301mV
475ps     155.9uV    277.1uV    69.41uV
[Falling Waveform]
R_fixture= 60.000
V_fixture= 1.200
V_fixture_min= 1.140
V_fixture_max= 1.270
|time   V(typ)   V(min)   V(max)
0s        1.199V     1.139V     1.27V
65ps      1.209V     1.146V     1.279V
84ps      1.191V     1.15V      1.254V
114ps     1.087V     1.131V     1.094V
144ps     911.7mV    1.058V     872.3mV
191ps     639.9mV    848.3mV    578.8mV
236ps     487.2mV    638.6mV    441.8mV
276ps     430.3mV    522.3mV    395.9mV
316ps     407mV      465.8mV    379.5mV
475ps     390.9mV    417.6mV    369.7mV
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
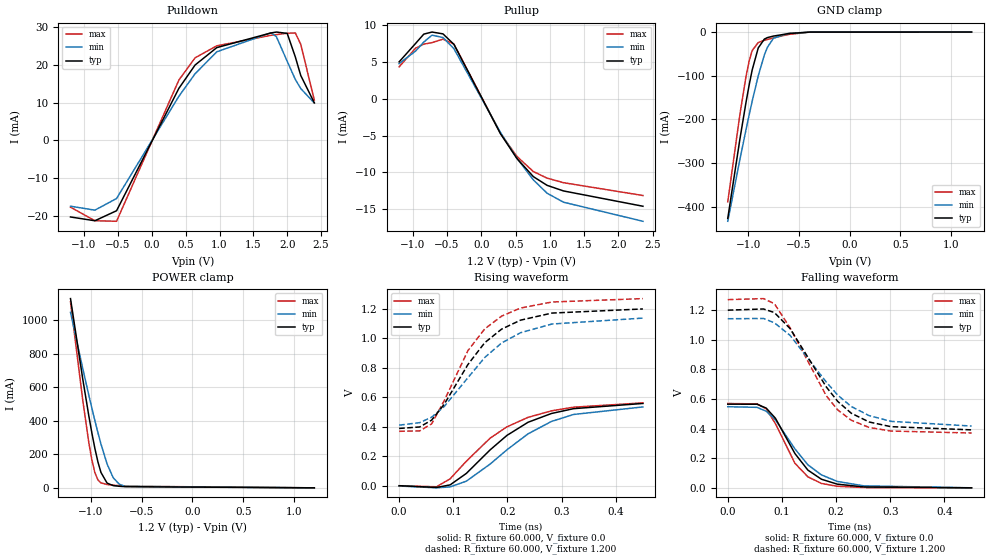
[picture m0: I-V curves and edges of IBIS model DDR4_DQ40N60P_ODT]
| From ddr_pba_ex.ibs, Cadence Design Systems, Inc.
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|   Model DDR4_DQ40N60P_ODT
[Model]   DDR4_DQ40N60P_ODT
Model_type I/O
Polarity   Non-Inverting
Enable   Active-High
Vinl   =   0.823V
Vinh   =   0.887V
C_comp   1.715pF   1.731pF   1.724pF
C_comp_pullup   0.538pF   0.595pF   0.525pF
C_comp_pulldown 1.177pF   1.135pF   1.198pF
[Model Spec]
Vinh   0.887V   NA   NA
Vinl   0.823V   NA   NA
Vmeas   0.840V   NA   NA
[Add Submodel]
|  Submodel_name   Mode
DDR4_DQ_ODT60   Non-Driving
[Temperature Range]   27.000   0.125k   -40.000
[Voltage Range]   1.200V   1.140V   1.270V
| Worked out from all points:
|   slope of the pulldown table from 0 to 0.18 V, typ, clamps not added: 27.2 ohm
|   slope of the pullup table from 0 to 0.18 V, typ, clamps not added: 57.4 ohm
|   GND clamp passes 1 mA (typ) near -0.50 V on its own axis
|   POWER clamp passes 1 mA (typ) near -0.46 V on its own axis
|   rising waveform, R_fixture 60.000, V_fixture 0.0: 20-80 % time 115ps typ, 121ps min, 116ps max; typ from 0.001 V to 0.558 V
|   rising waveform, R_fixture 60.000, V_fixture 1.200: 20-80 % time 95.9ps typ, 111ps min, 86ps max; typ from 0.389 V to 1.2 V
|   falling waveform, R_fixture 60.000, V_fixture 0.0: 20-80 % time 59.2ps typ, 70.8ps min, 50.4ps max; typ from 0.565 V to 0 V
|   falling waveform, R_fixture 60.000, V_fixture 1.200: 20-80 % time 89.3ps typ, 99.6ps min, 83.4ps max; typ from 1.2 V to 0.391 V
[Pulldown]
|Voltage   I(typ)   I(min)   I(max)
-1.2V     -20.33mA   -17.47mA   -17.73mA
-840mV    -21.33mA   -18.52mA   -21.33mA
-520mV    -18.67mA   -15.43mA   -21.47mA
400mV     13.8mA     11.7mA     16mA
640mV     20.01mA    17.69mA    21.92mA
960mV     24.62mA    23.51mA    25.09mA
1.76V     28.51mA    28.56mA    27.88mA
1.84V     28.75mA    27.53mA    28.07mA
2V        28.39mA    20.97mA    28.43mA
2.12V     22.12mA    16.15mA    28.51mA
2.2V      17.21mA    13.75mA    25.48mA
2.4V      9.967mA    9.905mA    10.69mA
[Pullup]
|Voltage   I(typ)   I(min)   I(max)
-1.2V     5.02mA     4.773mA    4.338mA
-960mV    7.516mA    6.485mA    6.876mA
-840mV    8.783mA    7.706mA    7.425mA
-720mV    9.066mA    8.641mA    7.63mA
-560mV    8.818mA    8.321mA    8.099mA
-400mV    7.394mA    6.807mA    7.432mA
280mV     -4.745mA   -4.576mA   -4.71mA
520mV     -8.111mA   -8.075mA   -7.827mA
760mV     -10.57mA   -11.01mA   -9.882mA
960mV     -11.75mA   -12.82mA   -10.77mA
1.2V      -12.51mA   -14.04mA   -11.39mA
2.36V     -14.59mA   -16.63mA   -13.13mA
[GND_clamp]
|Voltage   I(typ)   I(min)   I(max)
-1.2V     -426.2mA   -432.8mA   -388.3mA
-1.08V    -244.1mA   -290.9mA   -187.6mA
-1.02V    -160.2mA   -222.9mA   -101.2mA
-990mV    -121.8mA   -190.1mA   -66.76mA
-960mV    -87.12mA   -158.5mA   -42.47mA
-900mV    -36.37mA   -100.2mA   -23.99mA
-840mV    -16.17mA   -52.6mA    -18.98mA
-810mV    -12.75mA   -34.94mA   -17.06mA
-750mV    -9.219mA   -14.09mA   -13.42mA
-600mV    -3.476mA   -2.979mA   -5.372mA
-390mV    -77.95uA   -145.6uA   -88.64uA
1.2V      1.573nA    185.8nA    251.5pA
[POWER_clamp]
|Voltage   I(typ)   I(min)   I(max)
-1.2V     1.129A     1.047A     1.109A
-1.08V    651.1mA    713.3mA    524.8mA
-1.02V    430.1mA    553.1mA    270.8mA
-990mV    328mA      475.7mA    167mA
-960mV    234.7mA    400.6mA    90.32mA
-930mV    154.2mA    328.7mA    47.17mA
-900mV    91.53mA    260.8mA    29.3mA
-840mV    28.2mA     142.5mA    19.67mA
-780mV    13.3mA     60.49mA    15.94mA
-720mV    9.309mA    21.57mA    12.7mA
-660mV    6.902mA    8.818mA    9.642mA
1.2V      -4.11nA    -153.5nA   -872pA
[Ramp]
| variable   typ   min   max
dV/dt_r 0.301/0.112n   0.290/0.122n   0.299/0.111n
dV/dt_f 0.453/91.493p   0.403/0.102n   0.505/85.674p
R_load = 50.000
| The next line is not an IBIS keyword
| [Initial Delay]   0.325ns   0.535ns   0.200ns
[Rising Waveform]
R_fixture= 60.000
V_fixture= 0.0
V_fixture_min= 0.0
V_fixture_max= 0.0
|time   V(typ)   V(min)   V(max)
0s        1.44mV     -740.2uV   336.8uV
69ps      -10.7mV    -13.14mV   -5.941mV
94ps      6.685mV    -6.851mV   47.68mV
124ps     84.39mV    31.91mV    166.9mV
168ps     244.1mV    147.9mV    323.5mV
199ps     341.9mV    244.5mV    399.9mV
238ps     430.9mV    352.5mV    464.1mV
281ps     490.1mV    436.1mV    508mV
322ps     522.9mV    483.6mV    532.9mV
450ps     558.2mV    534.6mV    562.1mV
[Rising Waveform]
R_fixture= 60.000
V_fixture= 1.200
V_fixture_min= 1.140
V_fixture_max= 1.270
|time   V(typ)   V(min)   V(max)
0s        389mV      411.3mV    369.5mV
38ps      399mV      428.2mV    372.4mV
60ps      445.3mV    465.3mV    420.4mV
83ps      551.6mV    536.6mV    575.7mV
127ps     821.9mV    732.6mV    915.9mV
158ps     969.5mV    869.4mV    1.063V
189ps     1.061V     967.2mV    1.149V
224ps     1.122V     1.037V     1.204V
282ps     1.17V      1.096V     1.245V
450ps     1.198V     1.136V     1.268V
[Falling Waveform]
R_fixture= 60.000
V_fixture= 0.0
V_fixture_min= 0.0
V_fixture_max= 0.0
|time   V(typ)   V(min)   V(max)
0s        564.7mV    547.3mV    569mV
54ps      564.5mV    543.3mV    566.4mV
71ps      538mV      517.1mV    533.3mV
88ps      469.5mV    458.2mV    433.2mV
124ps     231.3mV    262.6mV    165.5mV
148ps     119.2mV    155mV      73.95mV
173ps     57.98mV    87.27mV    29.68mV
202ps     25.03mV    43.52mV    10.65mV
251ps     6.091mV    13.44mV    2.225mV
450ps     162.1uV    201.7uV    72.77uV
[Falling Waveform]
R_fixture= 60.000
V_fixture= 1.200
V_fixture_min= 1.140
V_fixture_max= 1.270
|time   V(typ)   V(min)   V(max)
0s        1.199V     1.141V     1.27V
66ps      1.207V     1.143V     1.277V
86ps      1.183V     1.114V     1.243V
115ps     1.075V     1.029V     1.08V
182ps     680.2mV    713.1mV    620.3mV
203ps     583.1mV    625.6mV    525.9mV
228ps     503.4mV    548.7mV    456mV
261ps     444.3mV    487.4mV    407.4mV
301ps     412.9mV    448.8mV    383.4mV
450ps     391.2mV    417mV      369.9mV
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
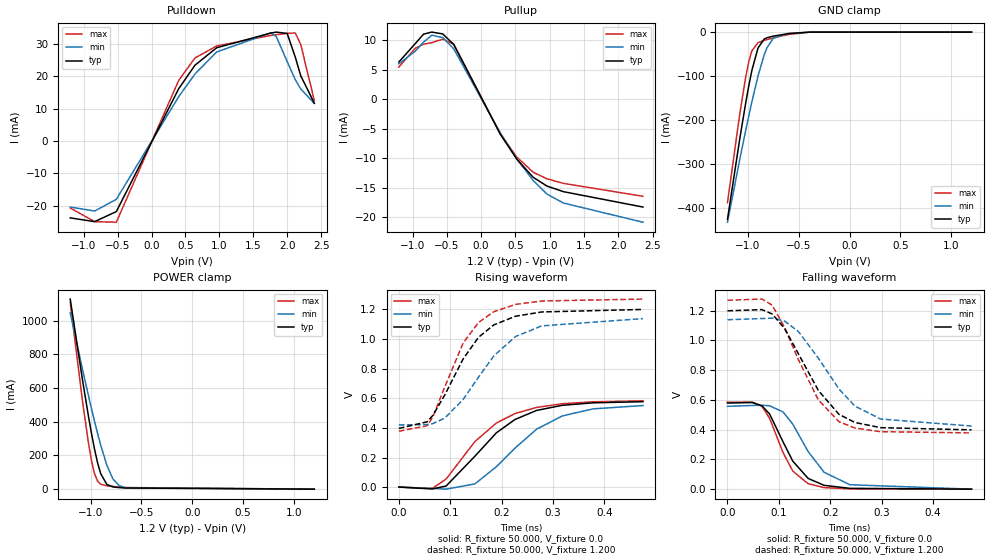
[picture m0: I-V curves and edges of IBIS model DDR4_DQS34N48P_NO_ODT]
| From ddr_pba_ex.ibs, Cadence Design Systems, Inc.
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|   Model DDR4_DQS34N48P_NO_ODT
[Model]   DDR4_DQS34N48P_NO_ODT
Model_type I/O
Polarity   Non-Inverting
Enable   Active-High
Vinl =  0.823V
Vinh =  0.887V
C_comp   1.693pF   1.693pF   1.716pF
C_comp_pullup   0.525pF   0.576pF   0.518pF
C_comp_pulldown   1.168pF   1.117pF   1.198pF
[Model Spec]
Vinh   0.887V   NA   NA
Vinl   0.823V   NA   NA
Vmeas   0.840V   NA   NA
[Temperature Range]   27.000   0.125k   -40.000
[Voltage Range]   1.200V   1.140V   1.270V
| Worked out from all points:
|   slope of the pulldown table from 0 to 0.18 V, typ, clamps not added: 23.3 ohm
|   slope of the pullup table from 0 to 0.18 V, typ, clamps not added: 45.9 ohm
|   GND clamp passes 1 mA (typ) near -0.50 V on its own axis
|   POWER clamp passes 1 mA (typ) near -0.46 V on its own axis
|   rising waveform, R_fixture 50.000, V_fixture 0.0: 20-80 % time 103ps typ, 110ps min, 100ps max; typ from 0.002 V to 0.578 V
|   rising waveform, R_fixture 50.000, V_fixture 1.200: 20-80 % time 83.6ps typ, 98.4ps min, 73ps max; typ from 0.397 V to 1.2 V
|   falling waveform, R_fixture 50.000, V_fixture 0.0: 20-80 % time 53.7ps typ, 63.6ps min, 45.1ps max; typ from 0.579 V to 0 V
|   falling waveform, R_fixture 50.000, V_fixture 1.200: 20-80 % time 81ps typ, 91.3ps min, 75.1ps max; typ from 1.2 V to 0.399 V
[Pulldown]
|Voltage   I(typ)   I(min)   I(max)
-1.2V     -23.72mA   -20.38mA   -20.68mA
-840mV    -24.88mA   -21.61mA   -24.88mA
-520mV    -21.78mA   -18mA      -25.05mA
400mV     16.1mA     13.66mA    18.67mA
640mV     23.35mA    20.64mA    25.58mA
960mV     28.73mA    27.44mA    29.28mA
1.76V     33.27mA    33.33mA    32.54mA
1.84V     33.56mA    32.14mA    32.76mA
2V        33.13mA    24.48mA    33.18mA
2.12V     25.82mA    18.86mA    33.28mA
2.2V      20.09mA    16.05mA    29.74mA
2.4V      11.64mA    11.56mA    12.48mA
[Pullup]
|Voltage   I(typ)   I(min)   I(max)
-1.2V     6.276mA    5.968mA    5.424mA
-960mV    9.395mA    8.108mA    8.597mA
-840mV    10.98mA    9.634mA    9.283mA
-720mV    11.33mA    10.8mA     9.54mA
-560mV    11.02mA    10.4mA     10.13mA
-400mV    9.244mA    8.51mA     9.292mA
280mV     -5.933mA   -5.721mA   -5.889mA
520mV     -10.14mA   -10.1mA    -9.786mA
760mV     -13.22mA   -13.77mA   -12.36mA
960mV     -14.69mA   -16.04mA   -13.47mA
1.2V      -15.64mA   -17.56mA   -14.24mA
2.36V     -18.24mA   -20.8mA    -16.42mA
[GND_clamp]
|Voltage   I(typ)   I(min)   I(max)
-1.2V     -426.2mA   -432.8mA   -388.3mA
-1.08V    -244.1mA   -290.9mA   -187.6mA
-1.02V    -160.2mA   -222.9mA   -101.2mA
-990mV    -121.8mA   -190.1mA   -66.76mA
-960mV    -87.12mA   -158.5mA   -42.47mA
-900mV    -36.37mA   -100.2mA   -23.99mA
-840mV    -16.17mA   -52.6mA    -18.98mA
-810mV    -12.75mA   -34.94mA   -17.06mA
-750mV    -9.219mA   -14.09mA   -13.42mA
-600mV    -3.476mA   -2.979mA   -5.372mA
-390mV    -77.95uA   -145.6uA   -88.64uA
1.2V      1.562nA    185.8nA    255.1pA
[POWER_clamp]
|Voltage   I(typ)   I(min)   I(max)
-1.2V     1.129A     1.047A     1.109A
-1.08V    651.1mA    713.3mA    524.8mA
-1.02V    430.1mA    553.1mA    270.8mA
-990mV    328mA      475.7mA    167mA
-960mV    234.7mA    400.6mA    90.32mA
-930mV    154.2mA    328.7mA    47.17mA
-900mV    91.53mA    260.8mA    29.3mA
-840mV    28.2mA     142.5mA    19.67mA
-780mV    13.3mA     60.49mA    15.94mA
-720mV    9.309mA    21.57mA    12.7mA
-660mV    6.902mA    8.818mA    9.642mA
1.2V      -4.11nA    -153.5nA   -871.8pA
[Ramp]
| variable   typ   min   max
dV/dt_r 0.348/0.105n   0.332/0.117n   0.351/0.105n
dV/dt_f 0.481/83.956p   0.430/97.879p   0.535/78.057p
R_load = 50.000
| The next line is not an IBIS keyword
| [Initial Delay]   0.325ns   0.500ns   0.200ns
[Rising Waveform]
R_fixture= 50.000
V_fixture= 0.0
V_fixture_min= 0.0
V_fixture_max= 0.0
|time   V(typ)   V(min)   V(max)
0s        1.711mV    1.158mV    451.4uV
65ps      -11.56mV   -7.321mV   -8.061mV
92ps      8.328mV    -12.86mV   55.58mV
148ps     209.5mV    22.65mV    308.6mV
190ps     368mV      139.1mV    434mV
226ps     457.4mV    264.3mV    497.4mV
268ps     518.5mV    391.6mV    538.6mV
318ps     553mV      481.4mV    563.8mV
378ps     569.8mV    529mV      576.8mV
475ps     577.5mV    551.4mV    583.4mV
[Rising Waveform]
R_fixture= 50.000
V_fixture= 1.200
V_fixture_min= 1.140
V_fixture_max= 1.270
|time   V(typ)   V(min)   V(max)
0s        397mV      420.5mV    378.1mV
55ps      441.7mV    423.1mV    415.2mV
66ps      484.5mV    429.8mV    472.7mV
89ps      620.6mV    465.5mV    673.9mV
125ps     865.5mV    591.9mV    972.8mV
155ps     1.012V     742.9mV    1.112V
185ps     1.096V     887.5mV    1.185V
227ps     1.154V     1.017V     1.234V
278ps     1.183V     1.089V     1.257V
475ps     1.2V       1.138V     1.27V
[Falling Waveform]
R_fixture= 50.000
V_fixture= 0.0
V_fixture_min= 0.0
V_fixture_max= 0.0
|time   V(typ)   V(min)   V(max)
0s        578.9mV    556.9mV    585.2mV
48ps      582.4mV    562.5mV    585.2mV
67ps      560.4mV    564.4mV    558.8mV
82ps      505.4mV    560.6mV    476.2mV
108ps     319mV      519.5mV    247.3mV
127ps     189mV      437.4mV    121.9mV
157ps     72.19mV    252.8mV    36.28mV
188ps     25.78mV    114mV      10.8mV
238ps     5.69mV     29.99mV    2.007mV
475ps     118uV      174.1uV    52.1uV
[Falling Waveform]
R_fixture= 50.000
V_fixture= 1.200
V_fixture_min= 1.140
V_fixture_max= 1.270
|time   V(typ)   V(min)   V(max)
0s        1.199V     1.139V     1.27V
67ps      1.207V     1.147V     1.278V
87ps      1.178V     1.15V      1.237V
111ps     1.081V     1.13V      1.088V
138ps     910.3mV    1.06V      870.8mV
177ps     662.7mV    880.3mV    599.1mV
217ps     503.1mV    673.4mV    453.9mV
248ps     448.4mV    558.4mV    411.2mV
298ps     413.5mV    471.5mV    386.5mV
475ps     398.7mV    424.4mV    378.1mV
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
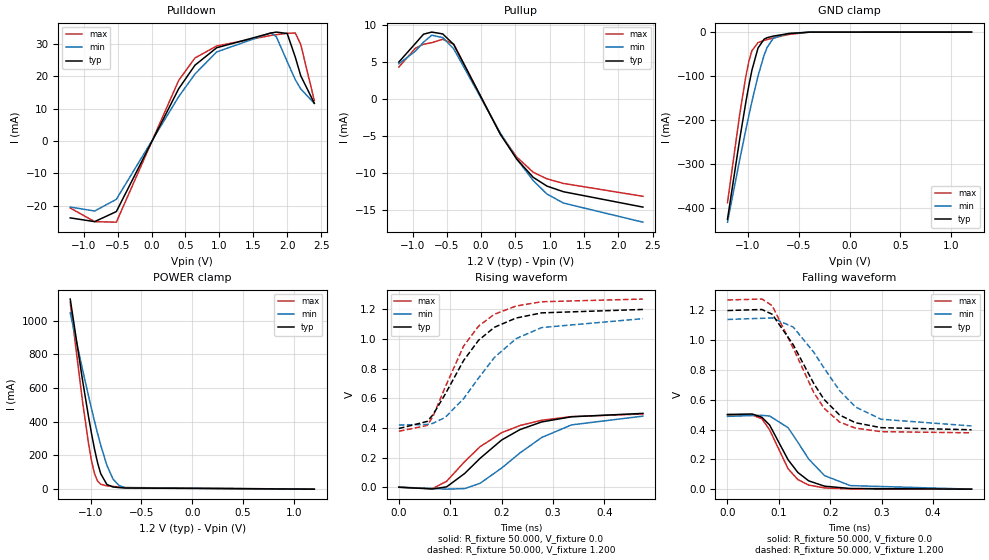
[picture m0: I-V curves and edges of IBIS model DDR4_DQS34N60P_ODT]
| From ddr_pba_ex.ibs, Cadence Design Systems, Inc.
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|   Model DDR4_DQS34N60P_ODT
[Model]   DDR4_DQS34N60P_ODT
Model_type I/O
Polarity   Non-Inverting
Enable   Active-High
Vinl =  0.823V
Vinh =  0.887V
C_comp   1.707pF   1.714pF   1.723pF
C_comp_pullup   0.536pF   0.593pF   0.525pF
C_comp_pulldown   1.170pF   1.121pF   1.198pF
[Model Spec]
Vinh   0.887V   NA   NA
Vinl   0.823V   NA   NA
Vmeas   0.840V   NA   NA
[Add Submodel]
|  Submodel_name   Mode
DDR4_DQS_ODT60   Non-Driving
[Temperature Range]   27.000   0.125k   -40.000
[Voltage Range]   1.200V   1.140V   1.270V
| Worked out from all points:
|   slope of the pulldown table from 0 to 0.18 V, typ, clamps not added: 23.3 ohm
|   slope of the pullup table from 0 to 0.18 V, typ, clamps not added: 57.4 ohm
|   GND clamp passes 1 mA (typ) near -0.50 V on its own axis
|   POWER clamp passes 1 mA (typ) near -0.46 V on its own axis
|   rising waveform, R_fixture 50.000, V_fixture 0.0: 20-80 % time 112ps typ, 118ps min, 109ps max; typ from 0.001 V to 0.499 V
|   rising waveform, R_fixture 50.000, V_fixture 1.200: 20-80 % time 90.8ps typ, 106ps min, 79.9ps max; typ from 0.397 V to 1.2 V
|   falling waveform, R_fixture 50.000, V_fixture 0.0: 20-80 % time 52.9ps typ, 63.7ps min, 44.3ps max; typ from 0.502 V to 0 V
|   falling waveform, R_fixture 50.000, V_fixture 1.200: 20-80 % time 81.4ps typ, 91.6ps min, 75.3ps max; typ from 1.2 V to 0.399 V
[Pulldown]
|Voltage   I(typ)   I(min)   I(max)
-1.2V     -23.72mA   -20.38mA   -20.68mA
-840mV    -24.88mA   -21.61mA   -24.88mA
-520mV    -21.78mA   -18mA      -25.05mA
400mV     16.1mA     13.66mA    18.67mA
640mV     23.35mA    20.64mA    25.58mA
960mV     28.73mA    27.44mA    29.28mA
1.76V     33.27mA    33.33mA    32.54mA
1.84V     33.56mA    32.14mA    32.76mA
2V        33.13mA    24.48mA    33.18mA
2.12V     25.82mA    18.86mA    33.28mA
2.2V      20.09mA    16.05mA    29.74mA
2.4V      11.64mA    11.56mA    12.48mA
[Pullup]
|Voltage   I(typ)   I(min)   I(max)
-1.2V     5.02mA     4.773mA    4.338mA
-960mV    7.516mA    6.485mA    6.876mA
-840mV    8.783mA    7.706mA    7.425mA
-720mV    9.066mA    8.641mA    7.63mA
-560mV    8.818mA    8.321mA    8.099mA
-400mV    7.394mA    6.807mA    7.432mA
280mV     -4.745mA   -4.576mA   -4.71mA
520mV     -8.111mA   -8.075mA   -7.827mA
760mV     -10.57mA   -11.01mA   -9.882mA
960mV     -11.75mA   -12.82mA   -10.77mA
1.2V      -12.51mA   -14.04mA   -11.39mA
2.36V     -14.59mA   -16.63mA   -13.13mA
[GND_clamp]
|Voltage   I(typ)   I(min)   I(max)
-1.2V     -426.2mA   -432.8mA   -388.3mA
-1.08V    -244.1mA   -290.9mA   -187.6mA
-1.02V    -160.2mA   -222.9mA   -101.2mA
-990mV    -121.8mA   -190.1mA   -66.76mA
-960mV    -87.12mA   -158.5mA   -42.47mA
-900mV    -36.37mA   -100.2mA   -23.99mA
-840mV    -16.17mA   -52.6mA    -18.98mA
-810mV    -12.75mA   -34.94mA   -17.06mA
-750mV    -9.219mA   -14.09mA   -13.42mA
-600mV    -3.476mA   -2.979mA   -5.372mA
-390mV    -77.95uA   -145.6uA   -88.64uA
1.2V      1.562nA    185.8nA    255.1pA
[POWER_clamp]
|Voltage   I(typ)   I(min)   I(max)
-1.2V     1.129A     1.047A     1.109A
-1.08V    651.1mA    713.3mA    524.8mA
-1.02V    430.1mA    553.1mA    270.8mA
-990mV    328mA      475.7mA    167mA
-960mV    234.7mA    400.6mA    90.32mA
-930mV    154.2mA    328.7mA    47.17mA
-900mV    91.53mA    260.8mA    29.3mA
-840mV    28.2mA     142.5mA    19.67mA
-780mV    13.3mA     60.49mA    15.94mA
-720mV    9.309mA    21.57mA    12.7mA
-660mV    6.902mA    8.818mA    9.642mA
1.2V      -4.11nA    -153.5nA   -871.8pA
[Ramp]
| variable   typ   min   max
dV/dt_r 0.301/0.116n   0.289/0.123n   0.299/0.114n
dV/dt_f 0.481/84.064p   0.430/98.706p   0.535/78.959p
R_load = 50.000
| The next line is not an IBIS keyword
| [Initial Delay]   0.325ns   0.500ns   0.200ns
[Rising Waveform]
R_fixture= 50.000
V_fixture= 0.0
V_fixture_min= 0.0
V_fixture_max= 0.0
|time   V(typ)   V(min)   V(max)
0s        1.436mV    1.024mV    409.4uV
65ps      -10.94mV   -6.683mV   -8.756mV
93ps      3.565mV    -12.06mV   41.08mV
128ps     93.45mV    -8.091mV   173.3mV
158ps     195.5mV    27.35mV    273.8mV
200ps     319.2mV    130.1mV    368.5mV
236ps     389.9mV    232.9mV    417.4mV
278ps     441mV      336.1mV    452.2mV
336ps     475.8mV    421.1mV    476.9mV
475ps     498.6mV    480.1mV    494.6mV
[Rising Waveform]
R_fixture= 50.000
V_fixture= 1.200
V_fixture_min= 1.140
V_fixture_max= 1.270
|time   V(typ)   V(min)   V(max)
0s        396.7mV    420.4mV    378.1mV
55ps      444.3mV    423.9mV    417.3mV
66ps      487.7mV    431.3mV    474.3mV
90ps      626.6mV    470.8mV    673.9mV
126ps     855mV      597.8mV    952mV
155ps     990.7mV    735.9mV    1.086V
186ps     1.079V     875.7mV    1.167V
228ps     1.141V     1.002V     1.222V
278ps     1.176V     1.077V     1.251V
475ps     1.199V     1.137V     1.269V
[Falling Waveform]
R_fixture= 50.000
V_fixture= 0.0
V_fixture_min= 0.0
V_fixture_max= 0.0
|time   V(typ)   V(min)   V(max)
0s        501.5mV    488.4mV    497.6mV
48ps      504.6mV    494.1mV    497.7mV
67ps      482.6mV    495.4mV    472.6mV
82ps      430.4mV    491.2mV    398mV
118ps     197mV      412.5mV    136.6mV
137ps     112.1mV    314.8mV    64.33mV
158ps     55.89mV    202.4mV    27.5mV
189ps     20.08mV    90.7mV     8.3mV
239ps     4.517mV    24.05mV    1.583mV
475ps     98.93uV    154.7uV    43.26uV
[Falling Waveform]
R_fixture= 50.000
V_fixture= 1.200
V_fixture_min= 1.140
V_fixture_max= 1.270
|time   V(typ)   V(min)   V(max)
0s        1.199V     1.139V     1.27V
67ps      1.206V     1.147V     1.276V
87ps      1.174V     1.149V     1.232V
128ps     969.3mV    1.088V     946.4mV
168ps     708.7mV    918.9mV    647.9mV
188ps     602.2mV    812.7mV    542.7mV
218ps     498.2mV    662.3mV    450.6mV
249ps     446mV      551.9mV    409.7mV
299ps     412.8mV    469.2mV    386.1mV
475ps     398.7mV    424.3mV    378.1mV
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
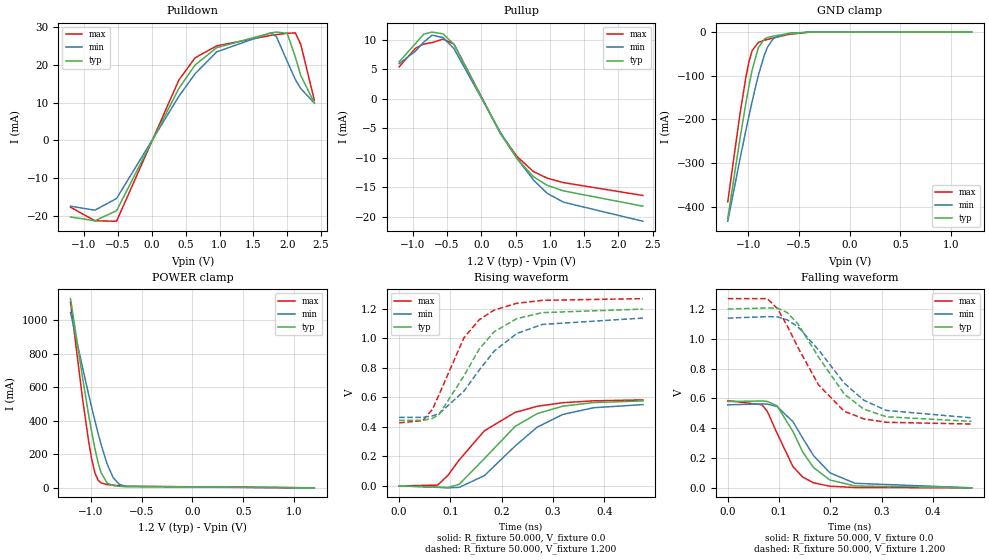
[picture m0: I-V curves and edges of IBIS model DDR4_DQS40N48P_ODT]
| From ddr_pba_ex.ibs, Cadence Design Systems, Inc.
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|   Model DDR4_DQS40N48P_ODT
[Model]   DDR4_DQS40N48P_ODT
Model_type I/O
Polarity   Non-Inverting
Enable   Active-High
Vinl =  0.823V
Vinh =  0.887V
C_comp   1.707pF   1.713pF   1.723pF
C_comp_pullup   0.527pF   0.579pF   0.519pF
C_comp_pulldown   1.180pF   1.134pF   1.204pF
[Model Spec]
Vinh   0.887V   NA   NA
Vinl   0.823V   NA   NA
Vmeas   0.840V   NA   NA
[Add Submodel]
|  Submodel_name   Mode
DDR4_DQS_ODT60   Non-Driving
[Temperature Range]   27.000   0.125k   -40.000
[Voltage Range]   1.200V   1.140V   1.270V
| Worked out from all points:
|   slope of the pulldown table from 0 to 0.18 V, typ, clamps not added: 27.2 ohm
|   slope of the pullup table from 0 to 0.18 V, typ, clamps not added: 45.9 ohm
|   GND clamp passes 1 mA (typ) near -0.50 V on its own axis
|   POWER clamp passes 1 mA (typ) near -0.46 V on its own axis
|   rising waveform, R_fixture 50.000, V_fixture 0.0: 20-80 % time 103ps typ, 110ps min, 100ps max; typ from 0 V to 0.577 V
|   rising waveform, R_fixture 50.000, V_fixture 1.200: 20-80 % time 83.7ps typ, 99.1ps min, 72.9ps max; typ from 0.445 V to 1.2 V
|   falling waveform, R_fixture 50.000, V_fixture 0.0: 20-80 % time 58.1ps typ, 68.4ps min, 49.4ps max; typ from 0.579 V to 0 V
|   falling waveform, R_fixture 50.000, V_fixture 1.200: 20-80 % time 89.4ps typ, 99.9ps min, 84.3ps max; typ from 1.2 V to 0.446 V
[Pulldown]
|Voltage   I(typ)   I(min)   I(max)
-1.2V     -20.33mA   -17.47mA   -17.73mA
-840mV    -21.33mA   -18.52mA   -21.33mA
-520mV    -18.67mA   -15.43mA   -21.47mA
400mV     13.8mA     11.7mA     16mA
640mV     20.01mA    17.69mA    21.92mA
960mV     24.62mA    23.51mA    25.09mA
1.76V     28.51mA    28.56mA    27.88mA
1.84V     28.75mA    27.53mA    28.07mA
2V        28.39mA    20.97mA    28.43mA
2.12V     22.12mA    16.15mA    28.52mA
2.2V      17.21mA    13.75mA    25.48mA
2.4V      9.967mA    9.905mA    10.69mA
[Pullup]
|Voltage   I(typ)   I(min)   I(max)
-1.2V     6.276mA    5.968mA    5.424mA
-960mV    9.396mA    8.108mA    8.597mA
-840mV    10.98mA    9.634mA    9.283mA
-720mV    11.33mA    10.8mA     9.54mA
-560mV    11.02mA    10.4mA     10.13mA
-400mV    9.244mA    8.51mA     9.292mA
280mV     -5.933mA   -5.721mA   -5.889mA
520mV     -10.14mA   -10.1mA    -9.786mA
760mV     -13.22mA   -13.77mA   -12.36mA
960mV     -14.69mA   -16.04mA   -13.47mA
1.2V      -15.64mA   -17.56mA   -14.24mA
2.36V     -18.24mA   -20.8mA    -16.42mA
[GND_clamp]
|Voltage   I(typ)   I(min)   I(max)
-1.2V     -426.2mA   -432.8mA   -388.3mA
-1.08V    -244.1mA   -290.9mA   -187.6mA
-1.02V    -160.2mA   -222.9mA   -101.2mA
-990mV    -121.8mA   -190.1mA   -66.76mA
-960mV    -87.12mA   -158.5mA   -42.47mA
-900mV    -36.37mA   -100.2mA   -23.99mA
-840mV    -16.17mA   -52.6mA    -18.98mA
-810mV    -12.75mA   -34.94mA   -17.06mA
-750mV    -9.219mA   -14.09mA   -13.42mA
-600mV    -3.476mA   -2.979mA   -5.372mA
-390mV    -77.95uA   -145.6uA   -88.64uA
1.2V      1.562nA    185.8nA    255.1pA
[POWER_clamp]
|Voltage   I(typ)   I(min)   I(max)
-1.2V     1.129A     1.047A     1.109A
-1.08V    651.1mA    713.3mA    524.8mA
-1.02V    430.1mA    553.1mA    270.8mA
-990mV    328mA      475.7mA    167mA
-960mV    234.7mA    400.6mA    90.32mA
-930mV    154.2mA    328.7mA    47.17mA
-900mV    91.53mA    260.8mA    29.3mA
-840mV    28.2mA     142.5mA    19.67mA
-780mV    13.3mA     60.49mA    15.94mA
-720mV    9.309mA    21.57mA    12.7mA
-660mV    6.902mA    8.818mA    9.642mA
1.2V      -4.11nA    -153.5nA   -871.8pA
[Ramp]
| variable   typ   min   max
dV/dt_r 0.348/0.105n   0.332/0.116n   0.351/0.105n
dV/dt_f 0.453/94.978p   0.403/0.104n   0.505/85.945p
R_load = 50.000
| The next line is not an IBIS keyword
| [Initial Delay]   0.300ns   0.500ns   0.200ns
[Rising Waveform]
R_fixture= 50.000
V_fixture= 0.0
V_fixture_min= 0.0
V_fixture_max= 0.0
|time   V(typ)   V(min)   V(max)
0s        369.8uV    1.134mV    452.1uV
75ps      -8.28mV    -9.428mV   5.873mV
95ps      -10.37mV   -12.66mV   71.55mV
117ps     11.27mV    -9.493mV   176.4mV
166ps     185.2mV    69.85mV    373.8mV
226ps     403.9mV    270.7mV    498.6mV
269ps     490.4mV    398.6mV    540mV
319ps     540.9mV    484.9mV    564.4mV
379ps     565.3mV    530.3mV    577.1mV
475ps     576.6mV    551.6mV    583.4mV
[Rising Waveform]
R_fixture= 50.000
V_fixture= 1.200
V_fixture_min= 1.140
V_fixture_max= 1.270
|time   V(typ)   V(min)   V(max)
0s        444.8mV    464.8mV    427.9mV
46ps      444.1mV    465.1mV    442.7mV
65ps      458.2mV    475.2mV    520.2mV
78ps      485.5mV    490.2mV    620.4mV
126ps     744.9mV    642.2mV    1.003V
156ps     927.7mV    785.3mV    1.127V
185ps     1.045V     913.5mV    1.192V
229ps     1.134V     1.033V     1.238V
279ps     1.175V     1.095V     1.258V
475ps     1.199V     1.138V     1.27V
[Falling Waveform]
R_fixture= 50.000
V_fixture= 0.0
V_fixture_min= 0.0
V_fixture_max= 0.0
|time   V(typ)   V(min)   V(max)
0s        579.3mV    557mV      585.2mV
67ps      582.9mV    563.3mV    557.3mV
77ps      580mV      561.6mV    513.5mV
96ps      550.6mV    545.5mV    367.1mV
127ps     378mV      444.2mV    142.4mV
146ps     240.5mV    334mV      72.52mV
167ps     136.9mV    216.8mV    33.63mV
199ps     52.77mV    100.9mV    10.92mV
248ps     12.5mV     30.38mV    2.348mV
475ps     173.6uV    242.9uV    61.55uV
[Falling Waveform]
R_fixture= 50.000
V_fixture= 1.200
V_fixture_min= 1.140
V_fixture_max= 1.270
|time   V(typ)   V(min)   V(max)
0s        1.2V       1.139V     1.27V
77ps      1.207V     1.149V     1.27V
97ps      1.206V     1.147V     1.202V
116ps     1.176V     1.127V     1.087V
137ps     1.099V     1.08V      940mV
177ps     876.8mV    925.5mV    690.1mV
227ps     629.1mV    702.1mV    513.6mV
265ps     528.4mV    588mV      463mV
309ps     477mV      519.6mV    440mV
475ps     446.1mV    469.7mV    428.1mV
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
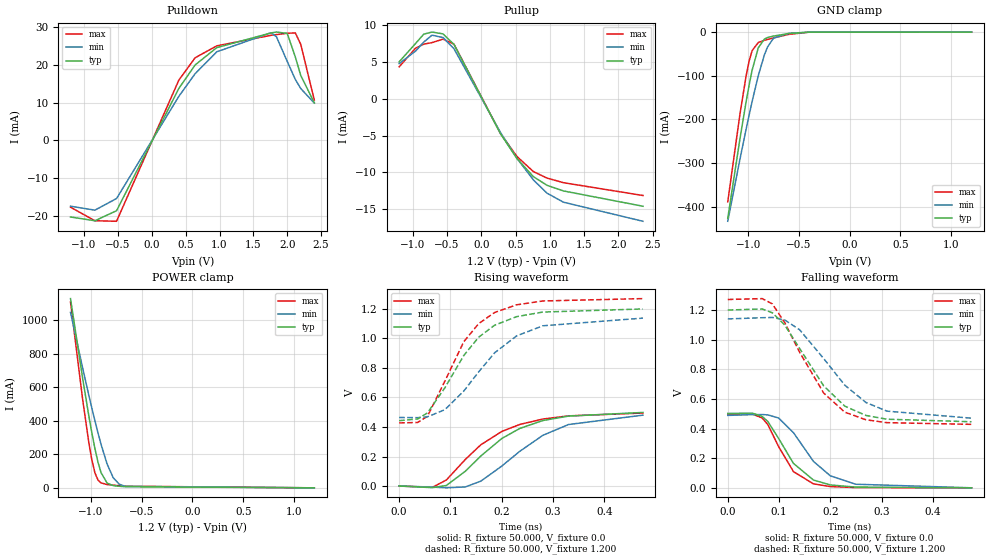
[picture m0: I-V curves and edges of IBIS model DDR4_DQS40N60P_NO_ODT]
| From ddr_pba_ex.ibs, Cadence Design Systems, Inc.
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|   Model DDR4_DQS40N60P_NO_ODT
[Model]   DDR4_DQS40N60P_NO_ODT
Model_type I/O
Polarity   Non-Inverting
Enable   Active-High
Vinl =  0.823V
Vinh =  0.887V
C_comp   1.720pF   1.734pF   1.730pF
C_comp_pullup   0.538pF   0.595pF   0.526pF
C_comp_pulldown   1.182pF   1.139pF   1.204pF
[Model Spec]
Vinh   0.887V   NA   NA
Vinl   0.823V   NA   NA
Vmeas   0.840V   NA   NA
[Temperature Range]   27.000   0.125k   -40.000
[Voltage Range]   1.200V   1.140V   1.270V
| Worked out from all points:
|   slope of the pulldown table from 0 to 0.18 V, typ, clamps not added: 27.2 ohm
|   slope of the pullup table from 0 to 0.18 V, typ, clamps not added: 57.4 ohm
|   GND clamp passes 1 mA (typ) near -0.50 V on its own axis
|   POWER clamp passes 1 mA (typ) near -0.46 V on its own axis
|   rising waveform, R_fixture 50.000, V_fixture 0.0: 20-80 % time 112ps typ, 118ps min, 109ps max; typ from 0.001 V to 0.499 V
|   rising waveform, R_fixture 50.000, V_fixture 1.200: 20-80 % time 91.2ps typ, 107ps min, 79.9ps max; typ from 0.443 V to 1.2 V
|   falling waveform, R_fixture 50.000, V_fixture 0.0: 20-80 % time 57.6ps typ, 68.4ps min, 48.5ps max; typ from 0.502 V to 0 V
|   falling waveform, R_fixture 50.000, V_fixture 1.200: 20-80 % time 89.7ps typ, 100ps min, 84.4ps max; typ from 1.2 V to 0.446 V
[Pulldown]
|Voltage   I(typ)   I(min)   I(max)
-1.2V     -20.33mA   -17.47mA   -17.73mA
-840mV    -21.33mA   -18.52mA   -21.33mA
-520mV    -18.67mA   -15.43mA   -21.47mA
400mV     13.8mA     11.7mA     16mA
640mV     20.01mA    17.69mA    21.92mA
960mV     24.62mA    23.51mA    25.09mA
1.76V     28.51mA    28.56mA    27.88mA
1.84V     28.75mA    27.53mA    28.07mA
2V        28.39mA    20.97mA    28.43mA
2.12V     22.12mA    16.15mA    28.51mA
2.2V      17.21mA    13.75mA    25.48mA
2.4V      9.967mA    9.905mA    10.69mA
[Pullup]
|Voltage   I(typ)   I(min)   I(max)
-1.2V     5.02mA     4.773mA    4.338mA
-960mV    7.514mA    6.485mA    6.876mA
-840mV    8.783mA    7.706mA    7.425mA
-720mV    9.066mA    8.641mA    7.63mA
-560mV    8.818mA    8.321mA    8.099mA
-400mV    7.394mA    6.807mA    7.432mA
280mV     -4.745mA   -4.576mA   -4.71mA
520mV     -8.111mA   -8.075mA   -7.827mA
760mV     -10.57mA   -11.01mA   -9.882mA
960mV     -11.75mA   -12.82mA   -10.77mA
1.2V      -12.51mA   -14.04mA   -11.39mA
2.36V     -14.59mA   -16.63mA   -13.13mA
[GND_clamp]
|Voltage   I(typ)   I(min)   I(max)
-1.2V     -426.2mA   -432.8mA   -388.3mA
-1.08V    -244.1mA   -290.9mA   -187.6mA
-1.02V    -160.2mA   -222.9mA   -101.2mA
-990mV    -121.8mA   -190.1mA   -66.76mA
-960mV    -87.12mA   -158.5mA   -42.47mA
-900mV    -36.37mA   -100.2mA   -23.99mA
-840mV    -16.17mA   -52.6mA    -18.98mA
-810mV    -12.75mA   -34.94mA   -17.06mA
-750mV    -9.219mA   -14.09mA   -13.42mA
-600mV    -3.476mA   -2.979mA   -5.372mA
-390mV    -77.95uA   -145.6uA   -88.64uA
1.2V      1.562nA    185.8nA    255.1pA
[POWER_clamp]
|Voltage   I(typ)   I(min)   I(max)
-1.2V     1.129A     1.047A     1.109A
-1.08V    651.1mA    713.3mA    524.8mA
-1.02V    430.1mA    553.1mA    270.8mA
-990mV    328mA      475.7mA    167mA
-960mV    234.7mA    400.6mA    90.32mA
-930mV    154.2mA    328.7mA    47.17mA
-900mV    91.53mA    260.8mA    29.3mA
-840mV    28.2mA     142.5mA    19.67mA
-780mV    13.3mA     60.49mA    15.94mA
-720mV    9.309mA    21.57mA    12.7mA
-660mV    6.902mA    8.818mA    9.642mA
1.2V      -4.11nA    -153.5nA   -871.8pA
[Ramp]
| variable   typ   min   max
dV/dt_r 0.301/0.116n   0.289/0.124n   0.299/0.114n
dV/dt_f 0.453/95.262p   0.403/0.105n   0.505/86.557p
R_load = 50.000
| The next line is not an IBIS keyword
| [Initial Delay]   0.325ns   0.500ns   0.200ns
[Rising Waveform]
R_fixture= 50.000
V_fixture= 0.0
V_fixture_min= 0.0
V_fixture_max= 0.0
|time   V(typ)   V(min)   V(max)
0s        1.431mV    990.4uV    403.8uV
65ps      -10.3mV    -6.386mV   -7.604mV
92ps      4.496mV    -11.39mV   41.65mV
129ps     101.2mV    -5.303mV   180.8mV
159ps     203.3mV    33.55mV    279.5mV
200ps     322.4mV    135.9mV    370.2mV
235ps     390.4mV    235.6mV    417.5mV
280ps     444mV      343.9mV    454mV
330ps     474mV      417mV      475.6mV
475ps     498.7mV    480.4mV    494.7mV
[Rising Waveform]
R_fixture= 50.000
V_fixture= 1.200
V_fixture_min= 1.140
V_fixture_max= 1.270
|time   V(typ)   V(min)   V(max)
0s        443.2mV    464.6mV    427.8mV
36ps      454.5mV    463.4mV    431mV
55ps      495.1mV    469.3mV    471.8mV
89ps      664.8mV    517mV      709.9mV
126ps     884.2mV    643.6mV    977.4mV
155ps     1.008V     773.4mV    1.1V
186ps     1.089V     902.2mV    1.175V
229ps     1.147V     1.017V     1.227V
280ps     1.178V     1.085V     1.253V
475ps     1.199V     1.137V     1.269V
[Falling Waveform]
R_fixture= 50.000
V_fixture= 0.0
V_fixture_min= 0.0
V_fixture_max= 0.0
|time   V(typ)   V(min)   V(max)
0s        501.6mV    488.5mV    497.6mV
48ps      503.7mV    493.7mV    497.2mV
67ps      481.4mV    494.2mV    471.4mV
78ps      447.8mV    491.9mV    426.5mV
99ps      333.5mV    470.9mV    278.5mV
128ps     164.7mV    371.9mV    109.3mV
167ps     52.55mV    178.3mV    26.75mV
200ps     19.49mV    80.66mV    8.46mV
249ps     5.068mV    24.42mV    1.852mV
475ps     117.5uV    212.5uV    51.07uV
[Falling Waveform]
R_fixture= 50.000
V_fixture= 1.200
V_fixture_min= 1.140
V_fixture_max= 1.270
|time   V(typ)   V(min)   V(max)
0s        1.199V     1.139V     1.27V
67ps      1.206V     1.147V     1.276V
87ps      1.18V      1.149V     1.24V
111ps     1.098V     1.132V     1.114V
140ps     939.8mV    1.066V     914.2mV
187ps     687mV      871.2mV    638.8mV
228ps     550.9mV    692.4mV    510.4mV
269ps     488.4mV    575.9mV    459.2mV
310ps     462.8mV    517.3mV    439.5mV
475ps     445.6mV    469.7mV    428.1mV
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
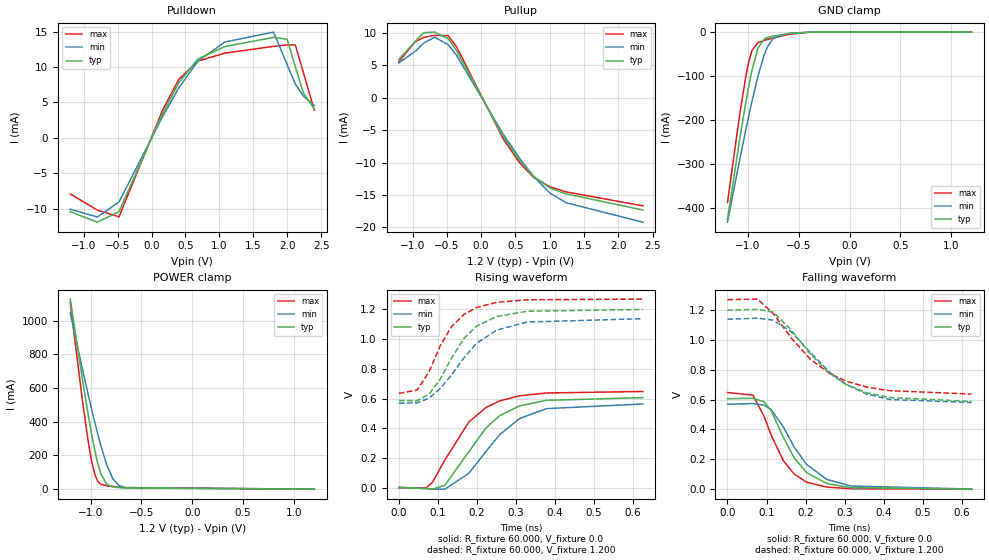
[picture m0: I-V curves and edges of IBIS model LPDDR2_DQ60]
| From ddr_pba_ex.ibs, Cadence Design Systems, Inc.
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|   Model LPDDR2_DQ60
[Model]   LPDDR2_DQ60
Model_type I/O
Enable   Active-High
Vinl   =   0.533V
Vinh   =   0.689V
C_comp   1.752pF   1.777pF   1.739pF
C_comp_pullup   0.551pF   0.596pF   0.519pF
C_comp_pulldown 1.200pF   1.180pF   1.220pF
[Model Spec]
Vinh   0.689V   NA   NA
Vinl   0.533V   NA   NA
Vmeas   0.600V   NA   NA
[Temperature Range]   27.000   0.125k   -40.000
[Voltage Range]   1.200V   1.140V   1.270V
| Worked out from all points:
|   slope of the pulldown table from 0 to 0.18 V, typ, clamps not added: 47.1 ohm
|   slope of the pullup table from 0 to 0.18 V, typ, clamps not added: 52.1 ohm
|   GND clamp passes 1 mA (typ) near -0.50 V on its own axis
|   POWER clamp passes 1 mA (typ) near -0.46 V on its own axis
|   rising waveform, R_fixture 60.000, V_fixture 0.0: 20-80 % time 108ps typ, 116ps min, 104ps max; typ from 0 V to 0.606 V
|   rising waveform, R_fixture 60.000, V_fixture 1.200: 20-80 % time 93.5ps typ, 114ps min, 81.5ps max; typ from 0.586 V to 1.2 V
|   falling waveform, R_fixture 60.000, V_fixture 0.0: 20-80 % time 78.5ps typ, 89ps min, 71.2ps max; typ from 0.606 V to 0 V
|   falling waveform, R_fixture 60.000, V_fixture 1.200: 20-80 % time 138ps typ, 136ps min, 143ps max; typ from 1.2 V to 0.588 V
[Pulldown]
|Voltage   I(typ)   I(min)   I(max)
-1.2V     -10.39mA   -10.04mA   -7.888mA
-800mV    -11.87mA   -11.14mA   -10.17mA
-480mV    -10.38mA   -9.014mA   -11.11mA
160mV     3.428mA    2.985mA    3.87mA
400mV     7.753mA    7.032mA    8.238mA
680mV     11.1mA     10.8mA     10.82mA
1.08V     12.88mA    13.52mA    11.95mA
1.8V      14.18mA    14.92mA    12.91mA
2V        13.9mA     10.31mA    13.11mA
2.12V     10.05mA    7.6mA      13.11mA
2.24V     6.348mA    5.886mA    9.172mA
2.4V      4.086mA    4.572mA    3.899mA
[Pullup]
|Voltage   I(typ)   I(min)   I(max)
-1.2V     5.931mA    5.398mA    5.591mA
-960mV    8.724mA    7.186mA    8.676mA
-840mV    10.05mA    8.422mA    9.316mA
-680mV    10.15mA    9.373mA    9.647mA
-480mV    9.135mA    8.197mA    9.587mA
-360mV    7.322mA    6.585mA    7.914mA
320mV     -5.937mA   -5.567mA   -6.303mA
560mV     -9.656mA   -9.326mA   -10.01mA
760mV     -12.08mA   -12.07mA   -12.23mA
1V        -13.89mA   -14.67mA   -13.72mA
1.24V     -14.83mA   -16.2mA    -14.52mA
2.36V     -17.32mA   -19.2mA    -16.68mA
[GND_clamp]
|Voltage   I(typ)   I(min)   I(max)
-1.2V     -426.2mA   -432.8mA   -388.3mA
-1.08V    -244.1mA   -290.9mA   -187.6mA
-1.02V    -160.2mA   -222.9mA   -101.2mA
-990mV    -121.8mA   -190.1mA   -66.76mA
-960mV    -87.12mA   -158.5mA   -42.47mA
-900mV    -36.37mA   -100.2mA   -23.99mA
-840mV    -16.17mA   -52.6mA    -18.98mA
-810mV    -12.75mA   -34.94mA   -17.06mA
-750mV    -9.218mA   -14.09mA   -13.42mA
-600mV    -3.476mA   -2.979mA   -5.372mA
-390mV    -77.95uA   -145.6uA   -88.64uA
1.2V      1.573nA    185.8nA    251.5pA
[POWER_clamp]
|Voltage   I(typ)   I(min)   I(max)
-1.2V     1.129A     1.047A     1.109A
-1.08V    651.1mA    713.3mA    524.8mA
-1.02V    430.1mA    553.1mA    270.8mA
-990mV    328mA      475.7mA    167mA
-960mV    234.7mA    400.6mA    90.32mA
-930mV    154.2mA    328.7mA    47.17mA
-900mV    91.53mA    260.8mA    29.3mA
-840mV    28.2mA     142.5mA    19.67mA
-780mV    13.3mA     60.49mA    15.94mA
-720mV    9.309mA    21.57mA    12.7mA
-660mV    6.902mA    8.818mA    9.642mA
1.2V      -4.11nA    -153.5nA   -872pA
[Ramp]
| variable   typ   min   max
dV/dt_r 0.327/0.103n   0.306/0.116n   0.347/97.810p
dV/dt_f 0.327/0.134n   0.302/0.134n   0.330/0.134n
R_load = 50.000
| The next line is not an IBIS keyword
| [Initial Delay]   0.300ns   0.500ns   0.200ns
[Rising Waveform]
R_fixture= 60.000
V_fixture= 0.0
V_fixture_min= 0.0
V_fixture_max= 0.0
|time   V(typ)   V(min)   V(max)
0s        325.7uV    1.027mV    327.7uV
70ps      -6.442mV   -6.978mV   -1.67mV
86ps      -10.62mV   -10.52mV   35.57mV
118ps     15.43mV    -10.41mV   186.2mV
179ps     241.4mV    95.86mV    441.1mV
224ps     404mV      246.6mV    541.2mV
258ps     484.3mV    355.8mV    583.6mV
309ps     550.6mV    465.2mV    618.4mV
378ps     587.7mV    531.9mV    637.4mV
625ps     606.1mV    563.3mV    647.5mV
[Rising Waveform]
R_fixture= 60.000
V_fixture= 1.200
V_fixture_min= 1.140
V_fixture_max= 1.270
|time   V(typ)   V(min)   V(max)
0s        586.4mV    568mV      635.1mV
47ps      585.3mV    571mV      656.7mV
78ps      630.5mV    602.9mV    783.4mV
106ps     731.5mV    667.2mV    956.2mV
135ps     873mV      758.8mV    1.085V
167ps     1.006V     875.3mV    1.167V
199ps     1.087V     971.8mV    1.213V
250ps     1.152V     1.06V      1.248V
328ps     1.188V     1.115V     1.265V
625ps     1.2V       1.138V     1.27V
[Falling Waveform]
R_fixture= 60.000
V_fixture= 0.0
V_fixture_min= 0.0
V_fixture_max= 0.0
|time   V(typ)   V(min)   V(max)
0s        606.4mV    569.1mV    647.6mV
65ps      608.7mV    573.8mV    630.2mV
93ps      587.2mV    563.6mV    492mV
112ps     524.3mV    533.2mV    361.4mV
143ps     348.2mV    417.5mV    191.3mV
171ps     208.7mV    281.4mV    100.5mV
203ps     110mV      165mV      46.63mV
255ps     37mV       64.8mV     13.74mV
316ps     10.3mV     21.29mV    3.375mV
625ps     53.64uV    769.2uV    43.71uV
[Falling Waveform]
R_fixture= 60.000
V_fixture= 1.200
V_fixture_min= 1.140
V_fixture_max= 1.270
|time   V(typ)   V(min)   V(max)
0s        1.2V       1.139V     1.27V
77ps      1.205V     1.146V     1.274V
117ps     1.187V     1.133V     1.178V
163ps     1.068V     1.056V     1.014V
212ps     906.2mV    917.4mV    871.3mV
261ps     777.2mV    785.6mV    776.9mV
302ps     704.2mV    704.5mV    725.4mV
356ps     645.7mV    637.5mV    684.2mV
416ps     613.5mV    601mV      659.8mV
625ps     588.2mV    580.6mV    637.4mV
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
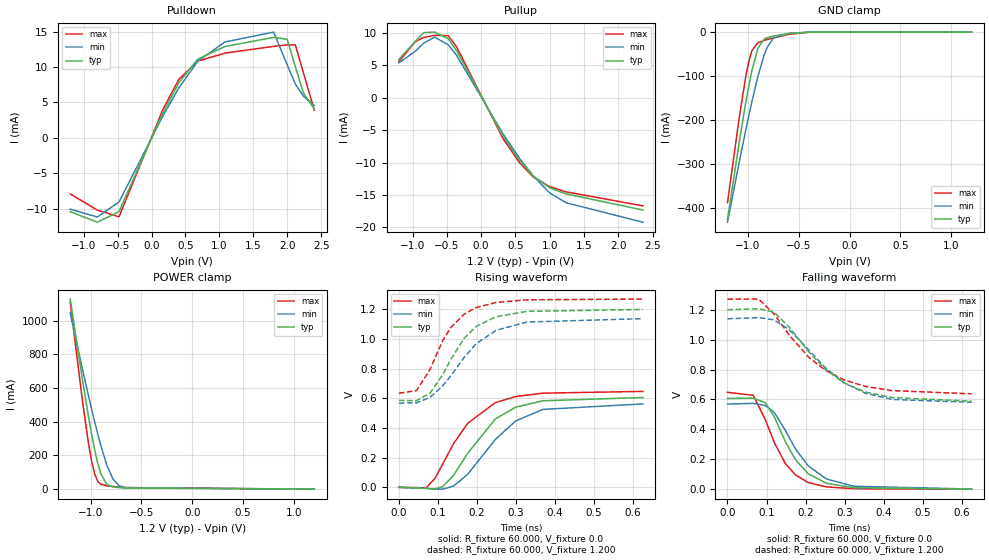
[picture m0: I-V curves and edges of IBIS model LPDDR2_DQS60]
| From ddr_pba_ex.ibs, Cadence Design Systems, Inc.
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|   Model LPDDR2_DQS60
[Model]   LPDDR2_DQS60
Model_type I/O
Enable   Active-High
Vinl   =   0.533V
Vinh   =   0.689V
C_comp   1.756pF   1.780pF   1.745pF
C_comp_pullup   0.551pF   0.596pF   0.519pF
C_comp_pulldown 1.205pF   1.184pF   1.225pF
[Model Spec]
Vinh   0.689V   NA   NA
Vinl   0.533V   NA   NA
Vmeas   0.600V   NA   NA
[Temperature Range]   27.000   0.125k   -40.000
[Voltage Range]   1.200V   1.140V   1.270V
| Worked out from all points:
|   slope of the pulldown table from 0 to 0.18 V, typ, clamps not added: 47.1 ohm
|   slope of the pullup table from 0 to 0.18 V, typ, clamps not added: 52.1 ohm
|   GND clamp passes 1 mA (typ) near -0.50 V on its own axis
|   POWER clamp passes 1 mA (typ) near -0.46 V on its own axis
|   rising waveform, R_fixture 60.000, V_fixture 0.0: 20-80 % time 108ps typ, 116ps min, 105ps max; typ from 0 V to 0.606 V
|   rising waveform, R_fixture 60.000, V_fixture 1.200: 20-80 % time 93.6ps typ, 114ps min, 81ps max; typ from 0.586 V to 1.2 V
|   falling waveform, R_fixture 60.000, V_fixture 0.0: 20-80 % time 79ps typ, 89.5ps min, 71.6ps max; typ from 0.606 V to 0 V
|   falling waveform, R_fixture 60.000, V_fixture 1.200: 20-80 % time 138ps typ, 136ps min, 144ps max; typ from 1.2 V to 0.588 V
[Pulldown]
|Voltage   I(typ)   I(min)   I(max)
-1.2V     -10.39mA   -10.04mA   -7.888mA
-800mV    -11.87mA   -11.14mA   -10.17mA
-480mV    -10.38mA   -9.014mA   -11.11mA
160mV     3.428mA    2.985mA    3.87mA
400mV     7.753mA    7.032mA    8.238mA
680mV     11.1mA     10.8mA     10.82mA
1.08V     12.88mA    13.52mA    11.95mA
1.8V      14.18mA    14.92mA    12.91mA
2V        13.9mA     10.31mA    13.11mA
2.12V     10.05mA    7.6mA      13.11mA
2.24V     6.348mA    5.886mA    9.172mA
2.4V      4.086mA    4.572mA    3.899mA
[Pullup]
|Voltage   I(typ)   I(min)   I(max)
-1.2V     5.931mA    5.398mA    5.591mA
-960mV    8.724mA    7.186mA    8.676mA
-840mV    10.05mA    8.422mA    9.316mA
-680mV    10.15mA    9.373mA    9.647mA
-480mV    9.135mA    8.197mA    9.587mA
-360mV    7.322mA    6.585mA    7.914mA
320mV     -5.937mA   -5.567mA   -6.303mA
560mV     -9.656mA   -9.326mA   -10.01mA
760mV     -12.08mA   -12.07mA   -12.23mA
1V        -13.89mA   -14.67mA   -13.72mA
1.24V     -14.83mA   -16.2mA    -14.52mA
2.36V     -17.32mA   -19.2mA    -16.68mA
[GND_clamp]
|Voltage   I(typ)   I(min)   I(max)
-1.2V     -426.2mA   -432.8mA   -388.3mA
-1.08V    -244.1mA   -290.9mA   -187.6mA
-1.02V    -160.2mA   -222.9mA   -101.2mA
-990mV    -121.8mA   -190.1mA   -66.76mA
-960mV    -87.12mA   -158.5mA   -42.47mA
-900mV    -36.37mA   -100.2mA   -23.99mA
-840mV    -16.17mA   -52.6mA    -18.98mA
-810mV    -12.75mA   -34.94mA   -17.06mA
-750mV    -9.218mA   -14.09mA   -13.42mA
-600mV    -3.476mA   -2.979mA   -5.372mA
-390mV    -77.95uA   -145.6uA   -88.64uA
1.2V      1.562nA    185.8nA    255.1pA
[POWER_clamp]
|Voltage   I(typ)   I(min)   I(max)
-1.2V     1.129A     1.047A     1.109A
-1.08V    651.1mA    713.3mA    524.8mA
-1.02V    430.1mA    553.1mA    270.8mA
-990mV    328mA      475.7mA    167mA
-960mV    234.7mA    400.6mA    90.32mA
-930mV    154.2mA    328.7mA    47.17mA
-900mV    91.53mA    260.8mA    29.3mA
-840mV    28.2mA     142.5mA    19.67mA
-780mV    13.3mA     60.49mA    15.94mA
-720mV    9.309mA    21.57mA    12.7mA
-660mV    6.902mA    8.818mA    9.642mA
1.2V      -4.11nA    -153.5nA   -871.8pA
[Ramp]
| variable   typ   min   max
dV/dt_r 0.327/0.105n   0.306/0.116n   0.347/99.558p
dV/dt_f 0.327/0.135n   0.302/0.134n   0.330/0.133n
R_load = 50.000
| The next line is not an IBIS keyword
| [Initial Delay]   0.300ns   0.500ns   0.200ns
[Rising Waveform]
R_fixture= 60.000
V_fixture= 0.0
V_fixture_min= 0.0
V_fixture_max= 0.0
|time   V(typ)   V(min)   V(max)
0s        320.4uV    1.04mV     334.1uV
70ps      -6.466mV   -7.01mV    -2.185mV
92ps      -10.99mV   -11.67mV   58.97mV
112ps     4.427mV    -11.95mV   155.6mV
140ps     81.19mV    8.548mV    294.6mV
176ps     229.3mV    87.67mV    430.9mV
247ps     461.3mV    323mV      571.3mV
299ps     540.7mV    447.9mV    612.5mV
369ps     584mV      526mV      635.5mV
625ps     606.1mV    562.9mV    647.4mV
[Rising Waveform]
R_fixture= 60.000
V_fixture= 1.200
V_fixture_min= 1.140
V_fixture_max= 1.270
|time   V(typ)   V(min)   V(max)
0s        586.4mV    568mV      635.1mV
45ps      584.8mV    570.3mV    652.4mV
80ps      635.7mV    606.5mV    796.3mV
112ps     758.7mV    684.5mV    988.3mV
132ps     857.7mV    748.6mV    1.075V
167ps     1.005V     875.5mV    1.168V
198ps     1.085V     969.1mV    1.213V
249ps     1.151V     1.059V     1.247V
328ps     1.187V     1.115V     1.265V
625ps     1.2V       1.138V     1.27V
[Falling Waveform]
R_fixture= 60.000
V_fixture= 0.0
V_fixture_min= 0.0
V_fixture_max= 0.0
|time   V(typ)   V(min)   V(max)
0s        606.4mV    569.1mV    647.6mV
66ps      608.8mV    573.7mV    627.6mV
97ps      578.4mV    559.6mV    464.5mV
120ps     482.8mV    512.2mV    310.8mV
148ps     319.5mV    394.2mV    172.1mV
174ps     197.1mV    269.6mV    95.39mV
207ps     102.5mV    155.2mV    43.69mV
253ps     39.87mV    68.72mV    15.27mV
323ps     9.559mV    19.75mV    3.179mV
625ps     58.27uV    886.8uV    44.65uV
[Falling Waveform]
R_fixture= 60.000
V_fixture= 1.200
V_fixture_min= 1.140
V_fixture_max= 1.270
|time   V(typ)   V(min)   V(max)
0s        1.2V       1.139V     1.27V
80ps      1.206V     1.147V     1.271V
119ps     1.184V     1.132V     1.172V
160ps     1.078V     1.063V     1.024V
208ps     919mV      930.2mV    881.9mV
250ps     803.2mV    813.8mV    795.9mV
298ps     710.8mV    712.2mV    730.7mV
353ps     649.2mV    641.5mV    687.2mV
422ps     612.1mV    599.6mV    658.9mV
625ps     588.3mV    581mV      637.5mV
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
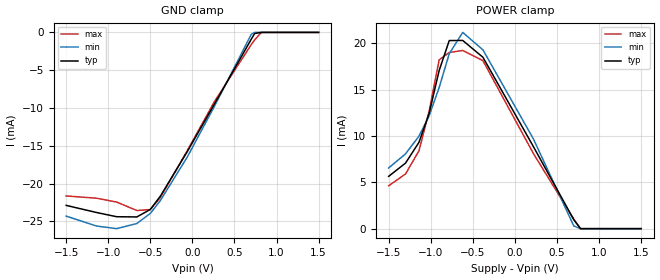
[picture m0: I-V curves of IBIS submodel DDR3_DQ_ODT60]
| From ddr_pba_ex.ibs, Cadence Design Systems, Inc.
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|   Submodel DDR3_DQ_ODT60
[Submodel]   DDR3_DQ_ODT60
Submodel_type Dynamic_clamp
[GND_clamp]
|Voltage   I(typ)   I(min)   I(max)
-1.5V     -22.89mA   -24.31mA   -21.64mA
-1.14V    -23.83mA   -25.62mA   -21.94mA
-900mV    -24.39mA   -25.97mA   -22.45mA
-660mV    -24.42mA   -25.29mA   -23.57mA
-500mV    -23.43mA   -23.96mA   -23.44mA
-380mV    -21.66mA   -22.24mA   -21.84mA
-60mV     -15.76mA   -16.48mA   -15.63mA
260mV     -9.521mA   -9.82mA    -9.192mA
700mV     -895.1uA   -247uA     -1.607mA
740mV     -142.1uA   50.33nA    -984.2uA
820mV     1.123nA    42.75nA    271pA
1.5V      -1.911nA   -275.5nA   -464.3pA
[POWER_clamp]
|Voltage   I(typ)   I(min)   I(max)
-1.5V     5.646mA    6.549mA    4.625mA
-1.3V     7.069mA    8.067mA    5.899mA
-1.14V    9.313mA    9.978mA    8.396mA
-1.02V    12.4mA     12.15mA    12.64mA
-900mV    17.06mA    15.23mA    18.22mA
-780mV    20.3mA     18.87mA    19.01mA
-620mV    20.31mA    21.18mA    19.23mA
-380mV    18.5mA     19.3mA     18.13mA
220mV     8.854mA    9.685mA    8.108mA
700mV     963.4uA    286.5uA    1.022mA
780mV     1.49nA     59.5nA     332.6pA
1.5V      5.523nA    199nA      1.165nA
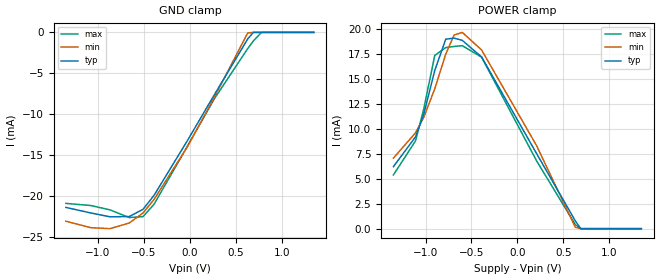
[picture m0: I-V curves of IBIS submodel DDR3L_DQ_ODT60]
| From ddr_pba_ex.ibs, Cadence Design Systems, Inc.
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|   Submodel DDR3L_DQ_ODT60
[Submodel]   DDR3L_DQ_ODT60
Submodel_type Dynamic_clamp
[GND_clamp]
|Voltage   I(typ)   I(min)   I(max)
-1.35V    -21.4mA    -23.09mA   -20.91mA
-1.08V    -22.08mA   -23.88mA   -21.17mA
-870mV    -22.55mA   -24mA      -21.7mA
-660mV    -22.52mA   -23.31mA   -22.64mA
-510mV    -21.63mA   -22.08mA   -22.53mA
-390mV    -19.92mA   -20.42mA   -21.01mA
-30mV     -13.29mA   -14.04mA   -13.97mA
270mV     -7.554mA   -7.852mA   -8.051mA
630mV     -797uA     -67.86uA   -1.983mA
690mV     1.232nA    43.59nA    -1.06mA
780mV     781.9pA    35.25nA    295.8pA
1.35V     -1.792nA   -307.1nA   -263.8pA
[POWER_clamp]
|Voltage   I(typ)   I(min)   I(max)
-1.35V    6.219mA    7.074mA    5.386mA
-1.11V    9.19mA     9.6mA      8.79mA
-1.02V    11.45mA    11.15mA    11.98mA
-900mV    15.85mA    14.01mA    17.36mA
-780mV    18.99mA    17.5mA     18.15mA
-690mV    19.1mA     19.4mA     18.26mA
-600mV    18.87mA    19.67mA    18.34mA
-390mV    17.21mA    17.91mA    17.19mA
210mV     7.511mA    8.303mA    6.779mA
630mV     794.1uA    144.3uA    419.5uA
690mV     1.349nA    54.04nA    219.2pA
1.35V     4.773nA    193.5nA    1.001nA
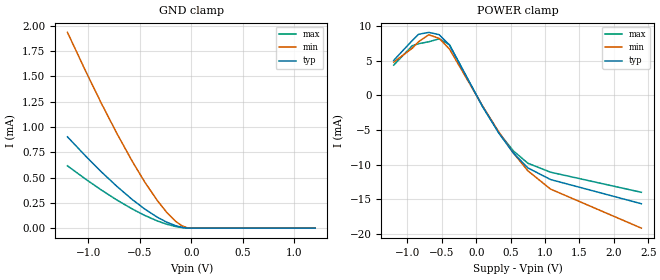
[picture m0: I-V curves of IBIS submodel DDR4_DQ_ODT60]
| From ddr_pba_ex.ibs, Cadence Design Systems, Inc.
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|   Submodel DDR4_DQ_ODT60
[Submodel]   DDR4_DQ_ODT60
Submodel_type Dynamic_clamp
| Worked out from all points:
|   POWER clamp passes 1 mA (typ) near -0.05 V on its own axis
[GND_clamp]
|Voltage   I(typ)   I(min)   I(max)
-1.2V     901.9uA    1.934mA    615.5uA
-1.02V    707.8uA    1.543mA    481.1uA
-870mV    554.6uA    1.23mA     375.5uA
-720mV    411.4uA    933.3uA    277.1uA
-570mV    280.7uA    656.4uA    187.9uA
-450mV    187.8uA    453.8uA    124.9uA
-330mV    108.2uA    273.6uA    71.42uA
-240mV    59.64uA    158.2uA    39.06uA
-150mV    23.26uA    65.9uA     15.09uA
-90mV     7.449uA    22.41uA    4.79uA
-30mV     4.655nA    128.3nA    1.014nA
1.2V      -1.573nA   -185.8nA   -251.5pA
[POWER_clamp]
|Voltage   I(typ)   I(min)   I(max)
-1.2V     5.019mA    4.771mA    4.338mA
-930mV    7.891mA    6.773mA    7.136mA
-840mV    8.783mA    7.706mA    7.425mA
-690mV    9.062mA    8.715mA    7.705mA
-540mV    8.732mA    8.194mA    8.134mA
-390mV    7.236mA    6.668mA    7.287mA
90mV      -1.606mA   -1.519mA   -1.625mA
330mV     -5.507mA   -5.342mA   -5.436mA
540mV     -8.355mA   -8.344mA   -8.041mA
750mV     -10.49mA   -10.91mA   -9.819mA
1.08V     -12.17mA   -13.55mA   -11.11mA
2.4V      -15.66mA   -19.18mA   -14.01mA
